VERSION 5.8 ;
BUSBITCHARS "[]" ;
DIVIDERCHAR "/" ;
UNITS
    DATABASE MICRONS 1000 ;
END UNITS

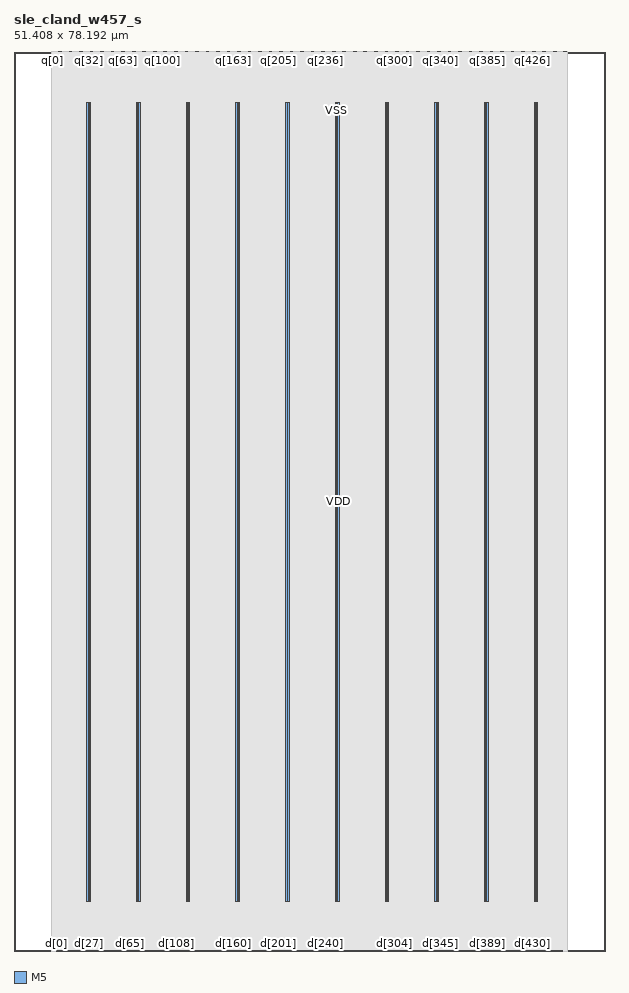
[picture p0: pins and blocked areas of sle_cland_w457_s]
MACRO sle_cland_w457_s
  FOREIGN sle_cland_w457_s 0 0 ;
  CLASS BLOCK ;
  SIZE 51.408 BY 78.192 ;
  PIN clk
    DIRECTION INPUT ;
    USE SIGNAL ;
    PORT
      LAYER M5 ;
        RECT  25.2 78.108 25.224 78.192 ;
    END
  END clk
  PIN d[0]
    DIRECTION INPUT ;
    USE SIGNAL ;
    PORT
      LAYER M5 ;
        RECT  3.696 0 3.72 0.084 ;
    END
  END d[0]
  PIN d[100]
    DIRECTION INPUT ;
    USE SIGNAL ;
    PORT
      LAYER M5 ;
        RECT  13.296 0 13.32 0.084 ;
    END
  END d[100]
  PIN d[101]
    DIRECTION INPUT ;
    USE SIGNAL ;
    PORT
      LAYER M5 ;
        RECT  13.392 0 13.416 0.084 ;
    END
  END d[101]
  PIN d[102]
    DIRECTION INPUT ;
    USE SIGNAL ;
    PORT
      LAYER M5 ;
        RECT  13.488 0 13.512 0.084 ;
    END
  END d[102]
  PIN d[103]
    DIRECTION INPUT ;
    USE SIGNAL ;
    PORT
      LAYER M5 ;
        RECT  13.584 0 13.608 0.084 ;
    END
  END d[103]
  PIN d[104]
    DIRECTION INPUT ;
    USE SIGNAL ;
    PORT
      LAYER M5 ;
        RECT  13.68 0 13.704 0.084 ;
    END
  END d[104]
  PIN d[105]
    DIRECTION INPUT ;
    USE SIGNAL ;
    PORT
      LAYER M5 ;
        RECT  13.776 0 13.8 0.084 ;
    END
  END d[105]
  PIN d[106]
    DIRECTION INPUT ;
    USE SIGNAL ;
    PORT
      LAYER M5 ;
        RECT  13.872 0 13.896 0.084 ;
    END
  END d[106]
  PIN d[107]
    DIRECTION INPUT ;
    USE SIGNAL ;
    PORT
      LAYER M5 ;
        RECT  13.968 0 13.992 0.084 ;
    END
  END d[107]
  PIN d[108]
    DIRECTION INPUT ;
    USE SIGNAL ;
    PORT
      LAYER M5 ;
        RECT  14.064 0 14.088 0.084 ;
    END
  END d[108]
  PIN d[109]
    DIRECTION INPUT ;
    USE SIGNAL ;
    PORT
      LAYER M5 ;
        RECT  14.16 0 14.184 0.084 ;
    END
  END d[109]
  PIN d[10]
    DIRECTION INPUT ;
    USE SIGNAL ;
    PORT
      LAYER M5 ;
        RECT  4.56 0 4.584 0.084 ;
    END
  END d[10]
  PIN d[110]
    DIRECTION INPUT ;
    USE SIGNAL ;
    PORT
      LAYER M5 ;
        RECT  14.256 0 14.28 0.084 ;
    END
  END d[110]
  PIN d[111]
    DIRECTION INPUT ;
    USE SIGNAL ;
    PORT
      LAYER M5 ;
        RECT  14.448 0 14.472 0.084 ;
    END
  END d[111]
  PIN d[112]
    DIRECTION INPUT ;
    USE SIGNAL ;
    PORT
      LAYER M5 ;
        RECT  14.352 0 14.376 0.084 ;
    END
  END d[112]
  PIN d[113]
    DIRECTION INPUT ;
    USE SIGNAL ;
    PORT
      LAYER M5 ;
        RECT  14.64 0 14.664 0.084 ;
    END
  END d[113]
  PIN d[114]
    DIRECTION INPUT ;
    USE SIGNAL ;
    PORT
      LAYER M5 ;
        RECT  14.544 0 14.568 0.084 ;
    END
  END d[114]
  PIN d[115]
    DIRECTION INPUT ;
    USE SIGNAL ;
    PORT
      LAYER M5 ;
        RECT  14.832 0 14.856 0.084 ;
    END
  END d[115]
  PIN d[116]
    DIRECTION INPUT ;
    USE SIGNAL ;
    PORT
      LAYER M5 ;
        RECT  14.736 0 14.76 0.084 ;
    END
  END d[116]
  PIN d[117]
    DIRECTION INPUT ;
    USE SIGNAL ;
    PORT
      LAYER M5 ;
        RECT  15.024 0 15.048 0.084 ;
    END
  END d[117]
  PIN d[118]
    DIRECTION INPUT ;
    USE SIGNAL ;
    PORT
      LAYER M5 ;
        RECT  14.928 0 14.952 0.084 ;
    END
  END d[118]
  PIN d[119]
    DIRECTION INPUT ;
    USE SIGNAL ;
    PORT
      LAYER M5 ;
        RECT  15.312 0 15.336 0.084 ;
    END
  END d[119]
  PIN d[11]
    DIRECTION INPUT ;
    USE SIGNAL ;
    PORT
      LAYER M5 ;
        RECT  4.848 0 4.872 0.084 ;
    END
  END d[11]
  PIN d[120]
    DIRECTION INPUT ;
    USE SIGNAL ;
    PORT
      LAYER M5 ;
        RECT  15.12 0 15.144 0.084 ;
    END
  END d[120]
  PIN d[121]
    DIRECTION INPUT ;
    USE SIGNAL ;
    PORT
      LAYER M5 ;
        RECT  15.408 0 15.432 0.084 ;
    END
  END d[121]
  PIN d[122]
    DIRECTION INPUT ;
    USE SIGNAL ;
    PORT
      LAYER M5 ;
        RECT  15.216 0 15.24 0.084 ;
    END
  END d[122]
  PIN d[123]
    DIRECTION INPUT ;
    USE SIGNAL ;
    PORT
      LAYER M5 ;
        RECT  15.6 0 15.624 0.084 ;
    END
  END d[123]
  PIN d[124]
    DIRECTION INPUT ;
    USE SIGNAL ;
    PORT
      LAYER M5 ;
        RECT  15.504 0 15.528 0.084 ;
    END
  END d[124]
  PIN d[125]
    DIRECTION INPUT ;
    USE SIGNAL ;
    PORT
      LAYER M5 ;
        RECT  15.792 0 15.816 0.084 ;
    END
  END d[125]
  PIN d[126]
    DIRECTION INPUT ;
    USE SIGNAL ;
    PORT
      LAYER M5 ;
        RECT  15.696 0 15.72 0.084 ;
    END
  END d[126]
  PIN d[127]
    DIRECTION INPUT ;
    USE SIGNAL ;
    PORT
      LAYER M5 ;
        RECT  16.08 0 16.104 0.084 ;
    END
  END d[127]
  PIN d[128]
    DIRECTION INPUT ;
    USE SIGNAL ;
    PORT
      LAYER M5 ;
        RECT  15.888 0 15.912 0.084 ;
    END
  END d[128]
  PIN d[129]
    DIRECTION INPUT ;
    USE SIGNAL ;
    PORT
      LAYER M5 ;
        RECT  16.176 0 16.2 0.084 ;
    END
  END d[129]
  PIN d[12]
    DIRECTION INPUT ;
    USE SIGNAL ;
    PORT
      LAYER M5 ;
        RECT  4.752 0 4.776 0.084 ;
    END
  END d[12]
  PIN d[130]
    DIRECTION INPUT ;
    USE SIGNAL ;
    PORT
      LAYER M5 ;
        RECT  15.984 0 16.008 0.084 ;
    END
  END d[130]
  PIN d[131]
    DIRECTION INPUT ;
    USE SIGNAL ;
    PORT
      LAYER M5 ;
        RECT  16.272 0 16.296 0.084 ;
    END
  END d[131]
  PIN d[132]
    DIRECTION INPUT ;
    USE SIGNAL ;
    PORT
      LAYER M5 ;
        RECT  16.464 0 16.488 0.084 ;
    END
  END d[132]
  PIN d[133]
    DIRECTION INPUT ;
    USE SIGNAL ;
    PORT
      LAYER M5 ;
        RECT  16.368 0 16.392 0.084 ;
    END
  END d[133]
  PIN d[134]
    DIRECTION INPUT ;
    USE SIGNAL ;
    PORT
      LAYER M5 ;
        RECT  16.656 0 16.68 0.084 ;
    END
  END d[134]
  PIN d[135]
    DIRECTION INPUT ;
    USE SIGNAL ;
    PORT
      LAYER M5 ;
        RECT  16.56 0 16.584 0.084 ;
    END
  END d[135]
  PIN d[136]
    DIRECTION INPUT ;
    USE SIGNAL ;
    PORT
      LAYER M5 ;
        RECT  16.848 0 16.872 0.084 ;
    END
  END d[136]
  PIN d[137]
    DIRECTION INPUT ;
    USE SIGNAL ;
    PORT
      LAYER M5 ;
        RECT  16.752 0 16.776 0.084 ;
    END
  END d[137]
  PIN d[138]
    DIRECTION INPUT ;
    USE SIGNAL ;
    PORT
      LAYER M5 ;
        RECT  17.04 0 17.064 0.084 ;
    END
  END d[138]
  PIN d[139]
    DIRECTION INPUT ;
    USE SIGNAL ;
    PORT
      LAYER M5 ;
        RECT  16.944 0 16.968 0.084 ;
    END
  END d[139]
  PIN d[13]
    DIRECTION INPUT ;
    USE SIGNAL ;
    PORT
      LAYER M5 ;
        RECT  5.04 0 5.064 0.084 ;
    END
  END d[13]
  PIN d[140]
    DIRECTION INPUT ;
    USE SIGNAL ;
    PORT
      LAYER M5 ;
        RECT  17.232 0 17.256 0.084 ;
    END
  END d[140]
  PIN d[141]
    DIRECTION INPUT ;
    USE SIGNAL ;
    PORT
      LAYER M5 ;
        RECT  17.136 0 17.16 0.084 ;
    END
  END d[141]
  PIN d[142]
    DIRECTION INPUT ;
    USE SIGNAL ;
    PORT
      LAYER M5 ;
        RECT  17.424 0 17.448 0.084 ;
    END
  END d[142]
  PIN d[143]
    DIRECTION INPUT ;
    USE SIGNAL ;
    PORT
      LAYER M5 ;
        RECT  17.328 0 17.352 0.084 ;
    END
  END d[143]
  PIN d[144]
    DIRECTION INPUT ;
    USE SIGNAL ;
    PORT
      LAYER M5 ;
        RECT  17.616 0 17.64 0.084 ;
    END
  END d[144]
  PIN d[145]
    DIRECTION INPUT ;
    USE SIGNAL ;
    PORT
      LAYER M5 ;
        RECT  17.52 0 17.544 0.084 ;
    END
  END d[145]
  PIN d[146]
    DIRECTION INPUT ;
    USE SIGNAL ;
    PORT
      LAYER M5 ;
        RECT  17.712 0 17.736 0.084 ;
    END
  END d[146]
  PIN d[147]
    DIRECTION INPUT ;
    USE SIGNAL ;
    PORT
      LAYER M5 ;
        RECT  17.808 0 17.832 0.084 ;
    END
  END d[147]
  PIN d[148]
    DIRECTION INPUT ;
    USE SIGNAL ;
    PORT
      LAYER M5 ;
        RECT  17.904 0 17.928 0.084 ;
    END
  END d[148]
  PIN d[149]
    DIRECTION INPUT ;
    USE SIGNAL ;
    PORT
      LAYER M5 ;
        RECT  18 0 18.024 0.084 ;
    END
  END d[149]
  PIN d[14]
    DIRECTION INPUT ;
    USE SIGNAL ;
    PORT
      LAYER M5 ;
        RECT  4.944 0 4.968 0.084 ;
    END
  END d[14]
  PIN d[150]
    DIRECTION INPUT ;
    USE SIGNAL ;
    PORT
      LAYER M5 ;
        RECT  18.096 0 18.12 0.084 ;
    END
  END d[150]
  PIN d[151]
    DIRECTION INPUT ;
    USE SIGNAL ;
    PORT
      LAYER M5 ;
        RECT  18.192 0 18.216 0.084 ;
    END
  END d[151]
  PIN d[152]
    DIRECTION INPUT ;
    USE SIGNAL ;
    PORT
      LAYER M5 ;
        RECT  18.288 0 18.312 0.084 ;
    END
  END d[152]
  PIN d[153]
    DIRECTION INPUT ;
    USE SIGNAL ;
    PORT
      LAYER M5 ;
        RECT  18.384 0 18.408 0.084 ;
    END
  END d[153]
  PIN d[154]
    DIRECTION INPUT ;
    USE SIGNAL ;
    PORT
      LAYER M5 ;
        RECT  18.48 0 18.504 0.084 ;
    END
  END d[154]
  PIN d[155]
    DIRECTION INPUT ;
    USE SIGNAL ;
    PORT
      LAYER M5 ;
        RECT  18.576 0 18.6 0.084 ;
    END
  END d[155]
  PIN d[156]
    DIRECTION INPUT ;
    USE SIGNAL ;
    PORT
      LAYER M5 ;
        RECT  18.672 0 18.696 0.084 ;
    END
  END d[156]
  PIN d[157]
    DIRECTION INPUT ;
    USE SIGNAL ;
    PORT
      LAYER M5 ;
        RECT  18.768 0 18.792 0.084 ;
    END
  END d[157]
  PIN d[158]
    DIRECTION INPUT ;
    USE SIGNAL ;
    PORT
      LAYER M5 ;
        RECT  18.864 0 18.888 0.084 ;
    END
  END d[158]
  PIN d[159]
    DIRECTION INPUT ;
    USE SIGNAL ;
    PORT
      LAYER M5 ;
        RECT  18.96 0 18.984 0.084 ;
    END
  END d[159]
  PIN d[15]
    DIRECTION INPUT ;
    USE SIGNAL ;
    PORT
      LAYER M5 ;
        RECT  5.232 0 5.256 0.084 ;
    END
  END d[15]
  PIN d[160]
    DIRECTION INPUT ;
    USE SIGNAL ;
    PORT
      LAYER M5 ;
        RECT  19.056 0 19.08 0.084 ;
    END
  END d[160]
  PIN d[161]
    DIRECTION INPUT ;
    USE SIGNAL ;
    PORT
      LAYER M5 ;
        RECT  19.152 0 19.176 0.084 ;
    END
  END d[161]
  PIN d[162]
    DIRECTION INPUT ;
    USE SIGNAL ;
    PORT
      LAYER M5 ;
        RECT  19.248 0 19.272 0.084 ;
    END
  END d[162]
  PIN d[163]
    DIRECTION INPUT ;
    USE SIGNAL ;
    PORT
      LAYER M5 ;
        RECT  19.44 0 19.464 0.084 ;
    END
  END d[163]
  PIN d[164]
    DIRECTION INPUT ;
    USE SIGNAL ;
    PORT
      LAYER M5 ;
        RECT  19.344 0 19.368 0.084 ;
    END
  END d[164]
  PIN d[165]
    DIRECTION INPUT ;
    USE SIGNAL ;
    PORT
      LAYER M5 ;
        RECT  19.632 0 19.656 0.084 ;
    END
  END d[165]
  PIN d[166]
    DIRECTION INPUT ;
    USE SIGNAL ;
    PORT
      LAYER M5 ;
        RECT  19.536 0 19.56 0.084 ;
    END
  END d[166]
  PIN d[167]
    DIRECTION INPUT ;
    USE SIGNAL ;
    PORT
      LAYER M5 ;
        RECT  19.824 0 19.848 0.084 ;
    END
  END d[167]
  PIN d[168]
    DIRECTION INPUT ;
    USE SIGNAL ;
    PORT
      LAYER M5 ;
        RECT  19.728 0 19.752 0.084 ;
    END
  END d[168]
  PIN d[169]
    DIRECTION INPUT ;
    USE SIGNAL ;
    PORT
      LAYER M5 ;
        RECT  20.112 0 20.136 0.084 ;
    END
  END d[169]
  PIN d[16]
    DIRECTION INPUT ;
    USE SIGNAL ;
    PORT
      LAYER M5 ;
        RECT  5.136 0 5.16 0.084 ;
    END
  END d[16]
  PIN d[170]
    DIRECTION INPUT ;
    USE SIGNAL ;
    PORT
      LAYER M5 ;
        RECT  19.92 0 19.944 0.084 ;
    END
  END d[170]
  PIN d[171]
    DIRECTION INPUT ;
    USE SIGNAL ;
    PORT
      LAYER M5 ;
        RECT  20.208 0 20.232 0.084 ;
    END
  END d[171]
  PIN d[172]
    DIRECTION INPUT ;
    USE SIGNAL ;
    PORT
      LAYER M5 ;
        RECT  20.016 0 20.04 0.084 ;
    END
  END d[172]
  PIN d[173]
    DIRECTION INPUT ;
    USE SIGNAL ;
    PORT
      LAYER M5 ;
        RECT  20.4 0 20.424 0.084 ;
    END
  END d[173]
  PIN d[174]
    DIRECTION INPUT ;
    USE SIGNAL ;
    PORT
      LAYER M5 ;
        RECT  20.304 0 20.328 0.084 ;
    END
  END d[174]
  PIN d[175]
    DIRECTION INPUT ;
    USE SIGNAL ;
    PORT
      LAYER M5 ;
        RECT  20.592 0 20.616 0.084 ;
    END
  END d[175]
  PIN d[176]
    DIRECTION INPUT ;
    USE SIGNAL ;
    PORT
      LAYER M5 ;
        RECT  20.496 0 20.52 0.084 ;
    END
  END d[176]
  PIN d[177]
    DIRECTION INPUT ;
    USE SIGNAL ;
    PORT
      LAYER M5 ;
        RECT  20.88 0 20.904 0.084 ;
    END
  END d[177]
  PIN d[178]
    DIRECTION INPUT ;
    USE SIGNAL ;
    PORT
      LAYER M5 ;
        RECT  20.688 0 20.712 0.084 ;
    END
  END d[178]
  PIN d[179]
    DIRECTION INPUT ;
    USE SIGNAL ;
    PORT
      LAYER M5 ;
        RECT  20.976 0 21 0.084 ;
    END
  END d[179]
  PIN d[17]
    DIRECTION INPUT ;
    USE SIGNAL ;
    PORT
      LAYER M5 ;
        RECT  5.424 0 5.448 0.084 ;
    END
  END d[17]
  PIN d[180]
    DIRECTION INPUT ;
    USE SIGNAL ;
    PORT
      LAYER M5 ;
        RECT  20.784 0 20.808 0.084 ;
    END
  END d[180]
  PIN d[181]
    DIRECTION INPUT ;
    USE SIGNAL ;
    PORT
      LAYER M5 ;
        RECT  21.072 0 21.096 0.084 ;
    END
  END d[181]
  PIN d[182]
    DIRECTION INPUT ;
    USE SIGNAL ;
    PORT
      LAYER M5 ;
        RECT  21.264 0 21.288 0.084 ;
    END
  END d[182]
  PIN d[183]
    DIRECTION INPUT ;
    USE SIGNAL ;
    PORT
      LAYER M5 ;
        RECT  21.168 0 21.192 0.084 ;
    END
  END d[183]
  PIN d[184]
    DIRECTION INPUT ;
    USE SIGNAL ;
    PORT
      LAYER M5 ;
        RECT  21.456 0 21.48 0.084 ;
    END
  END d[184]
  PIN d[185]
    DIRECTION INPUT ;
    USE SIGNAL ;
    PORT
      LAYER M5 ;
        RECT  21.36 0 21.384 0.084 ;
    END
  END d[185]
  PIN d[186]
    DIRECTION INPUT ;
    USE SIGNAL ;
    PORT
      LAYER M5 ;
        RECT  21.648 0 21.672 0.084 ;
    END
  END d[186]
  PIN d[187]
    DIRECTION INPUT ;
    USE SIGNAL ;
    PORT
      LAYER M5 ;
        RECT  21.552 0 21.576 0.084 ;
    END
  END d[187]
  PIN d[188]
    DIRECTION INPUT ;
    USE SIGNAL ;
    PORT
      LAYER M5 ;
        RECT  21.84 0 21.864 0.084 ;
    END
  END d[188]
  PIN d[189]
    DIRECTION INPUT ;
    USE SIGNAL ;
    PORT
      LAYER M5 ;
        RECT  21.744 0 21.768 0.084 ;
    END
  END d[189]
  PIN d[18]
    DIRECTION INPUT ;
    USE SIGNAL ;
    PORT
      LAYER M5 ;
        RECT  5.328 0 5.352 0.084 ;
    END
  END d[18]
  PIN d[190]
    DIRECTION INPUT ;
    USE SIGNAL ;
    PORT
      LAYER M5 ;
        RECT  22.032 0 22.056 0.084 ;
    END
  END d[190]
  PIN d[191]
    DIRECTION INPUT ;
    USE SIGNAL ;
    PORT
      LAYER M5 ;
        RECT  21.936 0 21.96 0.084 ;
    END
  END d[191]
  PIN d[192]
    DIRECTION INPUT ;
    USE SIGNAL ;
    PORT
      LAYER M5 ;
        RECT  22.224 0 22.248 0.084 ;
    END
  END d[192]
  PIN d[193]
    DIRECTION INPUT ;
    USE SIGNAL ;
    PORT
      LAYER M5 ;
        RECT  22.128 0 22.152 0.084 ;
    END
  END d[193]
  PIN d[194]
    DIRECTION INPUT ;
    USE SIGNAL ;
    PORT
      LAYER M5 ;
        RECT  22.32 0 22.344 0.084 ;
    END
  END d[194]
  PIN d[195]
    DIRECTION INPUT ;
    USE SIGNAL ;
    PORT
      LAYER M5 ;
        RECT  22.416 0 22.44 0.084 ;
    END
  END d[195]
  PIN d[196]
    DIRECTION INPUT ;
    USE SIGNAL ;
    PORT
      LAYER M5 ;
        RECT  22.512 0 22.536 0.084 ;
    END
  END d[196]
  PIN d[197]
    DIRECTION INPUT ;
    USE SIGNAL ;
    PORT
      LAYER M5 ;
        RECT  22.608 0 22.632 0.084 ;
    END
  END d[197]
  PIN d[198]
    DIRECTION INPUT ;
    USE SIGNAL ;
    PORT
      LAYER M5 ;
        RECT  22.704 0 22.728 0.084 ;
    END
  END d[198]
  PIN d[199]
    DIRECTION INPUT ;
    USE SIGNAL ;
    PORT
      LAYER M5 ;
        RECT  22.8 0 22.824 0.084 ;
    END
  END d[199]
  PIN d[19]
    DIRECTION INPUT ;
    USE SIGNAL ;
    PORT
      LAYER M5 ;
        RECT  5.616 0 5.64 0.084 ;
    END
  END d[19]
  PIN d[1]
    DIRECTION INPUT ;
    USE SIGNAL ;
    PORT
      LAYER M5 ;
        RECT  3.792 0 3.816 0.084 ;
    END
  END d[1]
  PIN d[200]
    DIRECTION INPUT ;
    USE SIGNAL ;
    PORT
      LAYER M5 ;
        RECT  22.896 0 22.92 0.084 ;
    END
  END d[200]
  PIN d[201]
    DIRECTION INPUT ;
    USE SIGNAL ;
    PORT
      LAYER M5 ;
        RECT  22.992 0 23.016 0.084 ;
    END
  END d[201]
  PIN d[202]
    DIRECTION INPUT ;
    USE SIGNAL ;
    PORT
      LAYER M5 ;
        RECT  23.088 0 23.112 0.084 ;
    END
  END d[202]
  PIN d[203]
    DIRECTION INPUT ;
    USE SIGNAL ;
    PORT
      LAYER M5 ;
        RECT  23.184 0 23.208 0.084 ;
    END
  END d[203]
  PIN d[204]
    DIRECTION INPUT ;
    USE SIGNAL ;
    PORT
      LAYER M5 ;
        RECT  23.28 0 23.304 0.084 ;
    END
  END d[204]
  PIN d[205]
    DIRECTION INPUT ;
    USE SIGNAL ;
    PORT
      LAYER M5 ;
        RECT  23.376 0 23.4 0.084 ;
    END
  END d[205]
  PIN d[206]
    DIRECTION INPUT ;
    USE SIGNAL ;
    PORT
      LAYER M5 ;
        RECT  23.472 0 23.496 0.084 ;
    END
  END d[206]
  PIN d[207]
    DIRECTION INPUT ;
    USE SIGNAL ;
    PORT
      LAYER M5 ;
        RECT  23.568 0 23.592 0.084 ;
    END
  END d[207]
  PIN d[208]
    DIRECTION INPUT ;
    USE SIGNAL ;
    PORT
      LAYER M5 ;
        RECT  23.664 0 23.688 0.084 ;
    END
  END d[208]
  PIN d[209]
    DIRECTION INPUT ;
    USE SIGNAL ;
    PORT
      LAYER M5 ;
        RECT  23.76 0 23.784 0.084 ;
    END
  END d[209]
  PIN d[20]
    DIRECTION INPUT ;
    USE SIGNAL ;
    PORT
      LAYER M5 ;
        RECT  5.52 0 5.544 0.084 ;
    END
  END d[20]
  PIN d[210]
    DIRECTION INPUT ;
    USE SIGNAL ;
    PORT
      LAYER M5 ;
        RECT  23.856 0 23.88 0.084 ;
    END
  END d[210]
  PIN d[211]
    DIRECTION INPUT ;
    USE SIGNAL ;
    PORT
      LAYER M5 ;
        RECT  23.952 0 23.976 0.084 ;
    END
  END d[211]
  PIN d[212]
    DIRECTION INPUT ;
    USE SIGNAL ;
    PORT
      LAYER M5 ;
        RECT  24.048 0 24.072 0.084 ;
    END
  END d[212]
  PIN d[213]
    DIRECTION INPUT ;
    USE SIGNAL ;
    PORT
      LAYER M5 ;
        RECT  24.24 0 24.264 0.084 ;
    END
  END d[213]
  PIN d[214]
    DIRECTION INPUT ;
    USE SIGNAL ;
    PORT
      LAYER M5 ;
        RECT  24.144 0 24.168 0.084 ;
    END
  END d[214]
  PIN d[215]
    DIRECTION INPUT ;
    USE SIGNAL ;
    PORT
      LAYER M5 ;
        RECT  24.432 0 24.456 0.084 ;
    END
  END d[215]
  PIN d[216]
    DIRECTION INPUT ;
    USE SIGNAL ;
    PORT
      LAYER M5 ;
        RECT  24.336 0 24.36 0.084 ;
    END
  END d[216]
  PIN d[217]
    DIRECTION INPUT ;
    USE SIGNAL ;
    PORT
      LAYER M5 ;
        RECT  24.624 0 24.648 0.084 ;
    END
  END d[217]
  PIN d[218]
    DIRECTION INPUT ;
    USE SIGNAL ;
    PORT
      LAYER M5 ;
        RECT  24.528 0 24.552 0.084 ;
    END
  END d[218]
  PIN d[219]
    DIRECTION INPUT ;
    USE SIGNAL ;
    PORT
      LAYER M5 ;
        RECT  24.912 0 24.936 0.084 ;
    END
  END d[219]
  PIN d[21]
    DIRECTION INPUT ;
    USE SIGNAL ;
    PORT
      LAYER M5 ;
        RECT  5.808 0 5.832 0.084 ;
    END
  END d[21]
  PIN d[220]
    DIRECTION INPUT ;
    USE SIGNAL ;
    PORT
      LAYER M5 ;
        RECT  24.72 0 24.744 0.084 ;
    END
  END d[220]
  PIN d[221]
    DIRECTION INPUT ;
    USE SIGNAL ;
    PORT
      LAYER M5 ;
        RECT  25.008 0 25.032 0.084 ;
    END
  END d[221]
  PIN d[222]
    DIRECTION INPUT ;
    USE SIGNAL ;
    PORT
      LAYER M5 ;
        RECT  24.816 0 24.84 0.084 ;
    END
  END d[222]
  PIN d[223]
    DIRECTION INPUT ;
    USE SIGNAL ;
    PORT
      LAYER M5 ;
        RECT  25.2 0 25.224 0.084 ;
    END
  END d[223]
  PIN d[224]
    DIRECTION INPUT ;
    USE SIGNAL ;
    PORT
      LAYER M5 ;
        RECT  25.104 0 25.128 0.084 ;
    END
  END d[224]
  PIN d[225]
    DIRECTION INPUT ;
    USE SIGNAL ;
    PORT
      LAYER M5 ;
        RECT  25.392 0 25.416 0.084 ;
    END
  END d[225]
  PIN d[226]
    DIRECTION INPUT ;
    USE SIGNAL ;
    PORT
      LAYER M5 ;
        RECT  25.296 0 25.32 0.084 ;
    END
  END d[226]
  PIN d[227]
    DIRECTION INPUT ;
    USE SIGNAL ;
    PORT
      LAYER M5 ;
        RECT  25.776 0 25.8 0.084 ;
    END
  END d[227]
  PIN d[228]
    DIRECTION INPUT ;
    USE SIGNAL ;
    PORT
      LAYER M5 ;
        RECT  25.488 0 25.512 0.084 ;
    END
  END d[228]
  PIN d[229]
    DIRECTION INPUT ;
    USE SIGNAL ;
    PORT
      LAYER M5 ;
        RECT  25.968 0 25.992 0.084 ;
    END
  END d[229]
  PIN d[22]
    DIRECTION INPUT ;
    USE SIGNAL ;
    PORT
      LAYER M5 ;
        RECT  5.712 0 5.736 0.084 ;
    END
  END d[22]
  PIN d[230]
    DIRECTION INPUT ;
    USE SIGNAL ;
    PORT
      LAYER M5 ;
        RECT  25.872 0 25.896 0.084 ;
    END
  END d[230]
  PIN d[231]
    DIRECTION INPUT ;
    USE SIGNAL ;
    PORT
      LAYER M5 ;
        RECT  26.064 0 26.088 0.084 ;
    END
  END d[231]
  PIN d[232]
    DIRECTION INPUT ;
    USE SIGNAL ;
    PORT
      LAYER M5 ;
        RECT  26.256 0 26.28 0.084 ;
    END
  END d[232]
  PIN d[233]
    DIRECTION INPUT ;
    USE SIGNAL ;
    PORT
      LAYER M5 ;
        RECT  26.16 0 26.184 0.084 ;
    END
  END d[233]
  PIN d[234]
    DIRECTION INPUT ;
    USE SIGNAL ;
    PORT
      LAYER M5 ;
        RECT  26.448 0 26.472 0.084 ;
    END
  END d[234]
  PIN d[235]
    DIRECTION INPUT ;
    USE SIGNAL ;
    PORT
      LAYER M5 ;
        RECT  26.352 0 26.376 0.084 ;
    END
  END d[235]
  PIN d[236]
    DIRECTION INPUT ;
    USE SIGNAL ;
    PORT
      LAYER M5 ;
        RECT  26.64 0 26.664 0.084 ;
    END
  END d[236]
  PIN d[237]
    DIRECTION INPUT ;
    USE SIGNAL ;
    PORT
      LAYER M5 ;
        RECT  26.544 0 26.568 0.084 ;
    END
  END d[237]
  PIN d[238]
    DIRECTION INPUT ;
    USE SIGNAL ;
    PORT
      LAYER M5 ;
        RECT  26.832 0 26.856 0.084 ;
    END
  END d[238]
  PIN d[239]
    DIRECTION INPUT ;
    USE SIGNAL ;
    PORT
      LAYER M5 ;
        RECT  26.736 0 26.76 0.084 ;
    END
  END d[239]
  PIN d[23]
    DIRECTION INPUT ;
    USE SIGNAL ;
    PORT
      LAYER M5 ;
        RECT  6 0 6.024 0.084 ;
    END
  END d[23]
  PIN d[240]
    DIRECTION INPUT ;
    USE SIGNAL ;
    PORT
      LAYER M5 ;
        RECT  27.024 0 27.048 0.084 ;
    END
  END d[240]
  PIN d[241]
    DIRECTION INPUT ;
    USE SIGNAL ;
    PORT
      LAYER M5 ;
        RECT  26.928 0 26.952 0.084 ;
    END
  END d[241]
  PIN d[242]
    DIRECTION INPUT ;
    USE SIGNAL ;
    PORT
      LAYER M5 ;
        RECT  27.216 0 27.24 0.084 ;
    END
  END d[242]
  PIN d[243]
    DIRECTION INPUT ;
    USE SIGNAL ;
    PORT
      LAYER M5 ;
        RECT  27.12 0 27.144 0.084 ;
    END
  END d[243]
  PIN d[244]
    DIRECTION INPUT ;
    USE SIGNAL ;
    PORT
      LAYER M5 ;
        RECT  27.312 0 27.336 0.084 ;
    END
  END d[244]
  PIN d[245]
    DIRECTION INPUT ;
    USE SIGNAL ;
    PORT
      LAYER M5 ;
        RECT  27.408 0 27.432 0.084 ;
    END
  END d[245]
  PIN d[246]
    DIRECTION INPUT ;
    USE SIGNAL ;
    PORT
      LAYER M5 ;
        RECT  27.6 0 27.624 0.084 ;
    END
  END d[246]
  PIN d[247]
    DIRECTION INPUT ;
    USE SIGNAL ;
    PORT
      LAYER M5 ;
        RECT  27.504 0 27.528 0.084 ;
    END
  END d[247]
  PIN d[248]
    DIRECTION INPUT ;
    USE SIGNAL ;
    PORT
      LAYER M5 ;
        RECT  27.792 0 27.816 0.084 ;
    END
  END d[248]
  PIN d[249]
    DIRECTION INPUT ;
    USE SIGNAL ;
    PORT
      LAYER M5 ;
        RECT  27.696 0 27.72 0.084 ;
    END
  END d[249]
  PIN d[24]
    DIRECTION INPUT ;
    USE SIGNAL ;
    PORT
      LAYER M5 ;
        RECT  5.904 0 5.928 0.084 ;
    END
  END d[24]
  PIN d[250]
    DIRECTION INPUT ;
    USE SIGNAL ;
    PORT
      LAYER M5 ;
        RECT  27.888 0 27.912 0.084 ;
    END
  END d[250]
  PIN d[251]
    DIRECTION INPUT ;
    USE SIGNAL ;
    PORT
      LAYER M5 ;
        RECT  27.984 0 28.008 0.084 ;
    END
  END d[251]
  PIN d[252]
    DIRECTION INPUT ;
    USE SIGNAL ;
    PORT
      LAYER M5 ;
        RECT  28.08 0 28.104 0.084 ;
    END
  END d[252]
  PIN d[253]
    DIRECTION INPUT ;
    USE SIGNAL ;
    PORT
      LAYER M5 ;
        RECT  28.176 0 28.2 0.084 ;
    END
  END d[253]
  PIN d[254]
    DIRECTION INPUT ;
    USE SIGNAL ;
    PORT
      LAYER M5 ;
        RECT  28.272 0 28.296 0.084 ;
    END
  END d[254]
  PIN d[255]
    DIRECTION INPUT ;
    USE SIGNAL ;
    PORT
      LAYER M5 ;
        RECT  28.368 0 28.392 0.084 ;
    END
  END d[255]
  PIN d[256]
    DIRECTION INPUT ;
    USE SIGNAL ;
    PORT
      LAYER M5 ;
        RECT  28.464 0 28.488 0.084 ;
    END
  END d[256]
  PIN d[257]
    DIRECTION INPUT ;
    USE SIGNAL ;
    PORT
      LAYER M5 ;
        RECT  28.56 0 28.584 0.084 ;
    END
  END d[257]
  PIN d[258]
    DIRECTION INPUT ;
    USE SIGNAL ;
    PORT
      LAYER M5 ;
        RECT  28.656 0 28.68 0.084 ;
    END
  END d[258]
  PIN d[259]
    DIRECTION INPUT ;
    USE SIGNAL ;
    PORT
      LAYER M5 ;
        RECT  28.752 0 28.776 0.084 ;
    END
  END d[259]
  PIN d[25]
    DIRECTION INPUT ;
    USE SIGNAL ;
    PORT
      LAYER M5 ;
        RECT  6.288 0 6.312 0.084 ;
    END
  END d[25]
  PIN d[260]
    DIRECTION INPUT ;
    USE SIGNAL ;
    PORT
      LAYER M5 ;
        RECT  28.848 0 28.872 0.084 ;
    END
  END d[260]
  PIN d[261]
    DIRECTION INPUT ;
    USE SIGNAL ;
    PORT
      LAYER M5 ;
        RECT  28.944 0 28.968 0.084 ;
    END
  END d[261]
  PIN d[262]
    DIRECTION INPUT ;
    USE SIGNAL ;
    PORT
      LAYER M5 ;
        RECT  29.04 0 29.064 0.084 ;
    END
  END d[262]
  PIN d[263]
    DIRECTION INPUT ;
    USE SIGNAL ;
    PORT
      LAYER M5 ;
        RECT  29.136 0 29.16 0.084 ;
    END
  END d[263]
  PIN d[264]
    DIRECTION INPUT ;
    USE SIGNAL ;
    PORT
      LAYER M5 ;
        RECT  29.232 0 29.256 0.084 ;
    END
  END d[264]
  PIN d[265]
    DIRECTION INPUT ;
    USE SIGNAL ;
    PORT
      LAYER M5 ;
        RECT  29.328 0 29.352 0.084 ;
    END
  END d[265]
  PIN d[266]
    DIRECTION INPUT ;
    USE SIGNAL ;
    PORT
      LAYER M5 ;
        RECT  29.424 0 29.448 0.084 ;
    END
  END d[266]
  PIN d[267]
    DIRECTION INPUT ;
    USE SIGNAL ;
    PORT
      LAYER M5 ;
        RECT  29.616 0 29.64 0.084 ;
    END
  END d[267]
  PIN d[268]
    DIRECTION INPUT ;
    USE SIGNAL ;
    PORT
      LAYER M5 ;
        RECT  29.52 0 29.544 0.084 ;
    END
  END d[268]
  PIN d[269]
    DIRECTION INPUT ;
    USE SIGNAL ;
    PORT
      LAYER M5 ;
        RECT  29.712 0 29.736 0.084 ;
    END
  END d[269]
  PIN d[26]
    DIRECTION INPUT ;
    USE SIGNAL ;
    PORT
      LAYER M5 ;
        RECT  6.096 0 6.12 0.084 ;
    END
  END d[26]
  PIN d[270]
    DIRECTION INPUT ;
    USE SIGNAL ;
    PORT
      LAYER M5 ;
        RECT  29.808 0 29.832 0.084 ;
    END
  END d[270]
  PIN d[271]
    DIRECTION INPUT ;
    USE SIGNAL ;
    PORT
      LAYER M5 ;
        RECT  30 0 30.024 0.084 ;
    END
  END d[271]
  PIN d[272]
    DIRECTION INPUT ;
    USE SIGNAL ;
    PORT
      LAYER M5 ;
        RECT  29.904 0 29.928 0.084 ;
    END
  END d[272]
  PIN d[273]
    DIRECTION INPUT ;
    USE SIGNAL ;
    PORT
      LAYER M5 ;
        RECT  30.192 0 30.216 0.084 ;
    END
  END d[273]
  PIN d[274]
    DIRECTION INPUT ;
    USE SIGNAL ;
    PORT
      LAYER M5 ;
        RECT  30.096 0 30.12 0.084 ;
    END
  END d[274]
  PIN d[275]
    DIRECTION INPUT ;
    USE SIGNAL ;
    PORT
      LAYER M5 ;
        RECT  30.384 0 30.408 0.084 ;
    END
  END d[275]
  PIN d[276]
    DIRECTION INPUT ;
    USE SIGNAL ;
    PORT
      LAYER M5 ;
        RECT  30.288 0 30.312 0.084 ;
    END
  END d[276]
  PIN d[277]
    DIRECTION INPUT ;
    USE SIGNAL ;
    PORT
      LAYER M5 ;
        RECT  30.576 0 30.6 0.084 ;
    END
  END d[277]
  PIN d[278]
    DIRECTION INPUT ;
    USE SIGNAL ;
    PORT
      LAYER M5 ;
        RECT  30.48 0 30.504 0.084 ;
    END
  END d[278]
  PIN d[279]
    DIRECTION INPUT ;
    USE SIGNAL ;
    PORT
      LAYER M5 ;
        RECT  30.768 0 30.792 0.084 ;
    END
  END d[279]
  PIN d[27]
    DIRECTION INPUT ;
    USE SIGNAL ;
    PORT
      LAYER M5 ;
        RECT  6.48 0 6.504 0.084 ;
    END
  END d[27]
  PIN d[280]
    DIRECTION INPUT ;
    USE SIGNAL ;
    PORT
      LAYER M5 ;
        RECT  30.672 0 30.696 0.084 ;
    END
  END d[280]
  PIN d[281]
    DIRECTION INPUT ;
    USE SIGNAL ;
    PORT
      LAYER M5 ;
        RECT  30.864 0 30.888 0.084 ;
    END
  END d[281]
  PIN d[282]
    DIRECTION INPUT ;
    USE SIGNAL ;
    PORT
      LAYER M5 ;
        RECT  31.056 0 31.08 0.084 ;
    END
  END d[282]
  PIN d[283]
    DIRECTION INPUT ;
    USE SIGNAL ;
    PORT
      LAYER M5 ;
        RECT  30.96 0 30.984 0.084 ;
    END
  END d[283]
  PIN d[284]
    DIRECTION INPUT ;
    USE SIGNAL ;
    PORT
      LAYER M5 ;
        RECT  31.248 0 31.272 0.084 ;
    END
  END d[284]
  PIN d[285]
    DIRECTION INPUT ;
    USE SIGNAL ;
    PORT
      LAYER M5 ;
        RECT  31.152 0 31.176 0.084 ;
    END
  END d[285]
  PIN d[286]
    DIRECTION INPUT ;
    USE SIGNAL ;
    PORT
      LAYER M5 ;
        RECT  31.44 0 31.464 0.084 ;
    END
  END d[286]
  PIN d[287]
    DIRECTION INPUT ;
    USE SIGNAL ;
    PORT
      LAYER M5 ;
        RECT  31.344 0 31.368 0.084 ;
    END
  END d[287]
  PIN d[288]
    DIRECTION INPUT ;
    USE SIGNAL ;
    PORT
      LAYER M5 ;
        RECT  31.632 0 31.656 0.084 ;
    END
  END d[288]
  PIN d[289]
    DIRECTION INPUT ;
    USE SIGNAL ;
    PORT
      LAYER M5 ;
        RECT  31.536 0 31.56 0.084 ;
    END
  END d[289]
  PIN d[28]
    DIRECTION INPUT ;
    USE SIGNAL ;
    PORT
      LAYER M5 ;
        RECT  6.192 0 6.216 0.084 ;
    END
  END d[28]
  PIN d[290]
    DIRECTION INPUT ;
    USE SIGNAL ;
    PORT
      LAYER M5 ;
        RECT  31.824 0 31.848 0.084 ;
    END
  END d[290]
  PIN d[291]
    DIRECTION INPUT ;
    USE SIGNAL ;
    PORT
      LAYER M5 ;
        RECT  31.728 0 31.752 0.084 ;
    END
  END d[291]
  PIN d[292]
    DIRECTION INPUT ;
    USE SIGNAL ;
    PORT
      LAYER M5 ;
        RECT  32.016 0 32.04 0.084 ;
    END
  END d[292]
  PIN d[293]
    DIRECTION INPUT ;
    USE SIGNAL ;
    PORT
      LAYER M5 ;
        RECT  31.92 0 31.944 0.084 ;
    END
  END d[293]
  PIN d[294]
    DIRECTION INPUT ;
    USE SIGNAL ;
    PORT
      LAYER M5 ;
        RECT  32.112 0 32.136 0.084 ;
    END
  END d[294]
  PIN d[295]
    DIRECTION INPUT ;
    USE SIGNAL ;
    PORT
      LAYER M5 ;
        RECT  32.208 0 32.232 0.084 ;
    END
  END d[295]
  PIN d[296]
    DIRECTION INPUT ;
    USE SIGNAL ;
    PORT
      LAYER M5 ;
        RECT  32.4 0 32.424 0.084 ;
    END
  END d[296]
  PIN d[297]
    DIRECTION INPUT ;
    USE SIGNAL ;
    PORT
      LAYER M5 ;
        RECT  32.304 0 32.328 0.084 ;
    END
  END d[297]
  PIN d[298]
    DIRECTION INPUT ;
    USE SIGNAL ;
    PORT
      LAYER M5 ;
        RECT  32.496 0 32.52 0.084 ;
    END
  END d[298]
  PIN d[299]
    DIRECTION INPUT ;
    USE SIGNAL ;
    PORT
      LAYER M5 ;
        RECT  32.592 0 32.616 0.084 ;
    END
  END d[299]
  PIN d[29]
    DIRECTION INPUT ;
    USE SIGNAL ;
    PORT
      LAYER M5 ;
        RECT  6.576 0 6.6 0.084 ;
    END
  END d[29]
  PIN d[2]
    DIRECTION INPUT ;
    USE SIGNAL ;
    PORT
      LAYER M5 ;
        RECT  3.888 0 3.912 0.084 ;
    END
  END d[2]
  PIN d[300]
    DIRECTION INPUT ;
    USE SIGNAL ;
    PORT
      LAYER M5 ;
        RECT  32.688 0 32.712 0.084 ;
    END
  END d[300]
  PIN d[301]
    DIRECTION INPUT ;
    USE SIGNAL ;
    PORT
      LAYER M5 ;
        RECT  32.784 0 32.808 0.084 ;
    END
  END d[301]
  PIN d[302]
    DIRECTION INPUT ;
    USE SIGNAL ;
    PORT
      LAYER M5 ;
        RECT  32.88 0 32.904 0.084 ;
    END
  END d[302]
  PIN d[303]
    DIRECTION INPUT ;
    USE SIGNAL ;
    PORT
      LAYER M5 ;
        RECT  32.976 0 33 0.084 ;
    END
  END d[303]
  PIN d[304]
    DIRECTION INPUT ;
    USE SIGNAL ;
    PORT
      LAYER M5 ;
        RECT  33.072 0 33.096 0.084 ;
    END
  END d[304]
  PIN d[305]
    DIRECTION INPUT ;
    USE SIGNAL ;
    PORT
      LAYER M5 ;
        RECT  33.168 0 33.192 0.084 ;
    END
  END d[305]
  PIN d[306]
    DIRECTION INPUT ;
    USE SIGNAL ;
    PORT
      LAYER M5 ;
        RECT  33.264 0 33.288 0.084 ;
    END
  END d[306]
  PIN d[307]
    DIRECTION INPUT ;
    USE SIGNAL ;
    PORT
      LAYER M5 ;
        RECT  33.36 0 33.384 0.084 ;
    END
  END d[307]
  PIN d[308]
    DIRECTION INPUT ;
    USE SIGNAL ;
    PORT
      LAYER M5 ;
        RECT  33.456 0 33.48 0.084 ;
    END
  END d[308]
  PIN d[309]
    DIRECTION INPUT ;
    USE SIGNAL ;
    PORT
      LAYER M5 ;
        RECT  33.552 0 33.576 0.084 ;
    END
  END d[309]
  PIN d[30]
    DIRECTION INPUT ;
    USE SIGNAL ;
    PORT
      LAYER M5 ;
        RECT  6.384 0 6.408 0.084 ;
    END
  END d[30]
  PIN d[310]
    DIRECTION INPUT ;
    USE SIGNAL ;
    PORT
      LAYER M5 ;
        RECT  33.648 0 33.672 0.084 ;
    END
  END d[310]
  PIN d[311]
    DIRECTION INPUT ;
    USE SIGNAL ;
    PORT
      LAYER M5 ;
        RECT  33.744 0 33.768 0.084 ;
    END
  END d[311]
  PIN d[312]
    DIRECTION INPUT ;
    USE SIGNAL ;
    PORT
      LAYER M5 ;
        RECT  33.84 0 33.864 0.084 ;
    END
  END d[312]
  PIN d[313]
    DIRECTION INPUT ;
    USE SIGNAL ;
    PORT
      LAYER M5 ;
        RECT  33.936 0 33.96 0.084 ;
    END
  END d[313]
  PIN d[314]
    DIRECTION INPUT ;
    USE SIGNAL ;
    PORT
      LAYER M5 ;
        RECT  34.032 0 34.056 0.084 ;
    END
  END d[314]
  PIN d[315]
    DIRECTION INPUT ;
    USE SIGNAL ;
    PORT
      LAYER M5 ;
        RECT  34.128 0 34.152 0.084 ;
    END
  END d[315]
  PIN d[316]
    DIRECTION INPUT ;
    USE SIGNAL ;
    PORT
      LAYER M5 ;
        RECT  34.224 0 34.248 0.084 ;
    END
  END d[316]
  PIN d[317]
    DIRECTION INPUT ;
    USE SIGNAL ;
    PORT
      LAYER M5 ;
        RECT  34.416 0 34.44 0.084 ;
    END
  END d[317]
  PIN d[318]
    DIRECTION INPUT ;
    USE SIGNAL ;
    PORT
      LAYER M5 ;
        RECT  34.32 0 34.344 0.084 ;
    END
  END d[318]
  PIN d[319]
    DIRECTION INPUT ;
    USE SIGNAL ;
    PORT
      LAYER M5 ;
        RECT  34.512 0 34.536 0.084 ;
    END
  END d[319]
  PIN d[31]
    DIRECTION INPUT ;
    USE SIGNAL ;
    PORT
      LAYER M5 ;
        RECT  6.672 0 6.696 0.084 ;
    END
  END d[31]
  PIN d[320]
    DIRECTION INPUT ;
    USE SIGNAL ;
    PORT
      LAYER M5 ;
        RECT  34.608 0 34.632 0.084 ;
    END
  END d[320]
  PIN d[321]
    DIRECTION INPUT ;
    USE SIGNAL ;
    PORT
      LAYER M5 ;
        RECT  34.8 0 34.824 0.084 ;
    END
  END d[321]
  PIN d[322]
    DIRECTION INPUT ;
    USE SIGNAL ;
    PORT
      LAYER M5 ;
        RECT  34.704 0 34.728 0.084 ;
    END
  END d[322]
  PIN d[323]
    DIRECTION INPUT ;
    USE SIGNAL ;
    PORT
      LAYER M5 ;
        RECT  34.992 0 35.016 0.084 ;
    END
  END d[323]
  PIN d[324]
    DIRECTION INPUT ;
    USE SIGNAL ;
    PORT
      LAYER M5 ;
        RECT  34.896 0 34.92 0.084 ;
    END
  END d[324]
  PIN d[325]
    DIRECTION INPUT ;
    USE SIGNAL ;
    PORT
      LAYER M5 ;
        RECT  35.184 0 35.208 0.084 ;
    END
  END d[325]
  PIN d[326]
    DIRECTION INPUT ;
    USE SIGNAL ;
    PORT
      LAYER M5 ;
        RECT  35.088 0 35.112 0.084 ;
    END
  END d[326]
  PIN d[327]
    DIRECTION INPUT ;
    USE SIGNAL ;
    PORT
      LAYER M5 ;
        RECT  35.376 0 35.4 0.084 ;
    END
  END d[327]
  PIN d[328]
    DIRECTION INPUT ;
    USE SIGNAL ;
    PORT
      LAYER M5 ;
        RECT  35.28 0 35.304 0.084 ;
    END
  END d[328]
  PIN d[329]
    DIRECTION INPUT ;
    USE SIGNAL ;
    PORT
      LAYER M5 ;
        RECT  35.568 0 35.592 0.084 ;
    END
  END d[329]
  PIN d[32]
    DIRECTION INPUT ;
    USE SIGNAL ;
    PORT
      LAYER M5 ;
        RECT  6.864 0 6.888 0.084 ;
    END
  END d[32]
  PIN d[330]
    DIRECTION INPUT ;
    USE SIGNAL ;
    PORT
      LAYER M5 ;
        RECT  35.472 0 35.496 0.084 ;
    END
  END d[330]
  PIN d[331]
    DIRECTION INPUT ;
    USE SIGNAL ;
    PORT
      LAYER M5 ;
        RECT  35.76 0 35.784 0.084 ;
    END
  END d[331]
  PIN d[332]
    DIRECTION INPUT ;
    USE SIGNAL ;
    PORT
      LAYER M5 ;
        RECT  35.664 0 35.688 0.084 ;
    END
  END d[332]
  PIN d[333]
    DIRECTION INPUT ;
    USE SIGNAL ;
    PORT
      LAYER M5 ;
        RECT  35.856 0 35.88 0.084 ;
    END
  END d[333]
  PIN d[334]
    DIRECTION INPUT ;
    USE SIGNAL ;
    PORT
      LAYER M5 ;
        RECT  36.048 0 36.072 0.084 ;
    END
  END d[334]
  PIN d[335]
    DIRECTION INPUT ;
    USE SIGNAL ;
    PORT
      LAYER M5 ;
        RECT  35.952 0 35.976 0.084 ;
    END
  END d[335]
  PIN d[336]
    DIRECTION INPUT ;
    USE SIGNAL ;
    PORT
      LAYER M5 ;
        RECT  36.24 0 36.264 0.084 ;
    END
  END d[336]
  PIN d[337]
    DIRECTION INPUT ;
    USE SIGNAL ;
    PORT
      LAYER M5 ;
        RECT  36.144 0 36.168 0.084 ;
    END
  END d[337]
  PIN d[338]
    DIRECTION INPUT ;
    USE SIGNAL ;
    PORT
      LAYER M5 ;
        RECT  36.432 0 36.456 0.084 ;
    END
  END d[338]
  PIN d[339]
    DIRECTION INPUT ;
    USE SIGNAL ;
    PORT
      LAYER M5 ;
        RECT  36.336 0 36.36 0.084 ;
    END
  END d[339]
  PIN d[33]
    DIRECTION INPUT ;
    USE SIGNAL ;
    PORT
      LAYER M5 ;
        RECT  6.768 0 6.792 0.084 ;
    END
  END d[33]
  PIN d[340]
    DIRECTION INPUT ;
    USE SIGNAL ;
    PORT
      LAYER M5 ;
        RECT  36.624 0 36.648 0.084 ;
    END
  END d[340]
  PIN d[341]
    DIRECTION INPUT ;
    USE SIGNAL ;
    PORT
      LAYER M5 ;
        RECT  36.528 0 36.552 0.084 ;
    END
  END d[341]
  PIN d[342]
    DIRECTION INPUT ;
    USE SIGNAL ;
    PORT
      LAYER M5 ;
        RECT  36.816 0 36.84 0.084 ;
    END
  END d[342]
  PIN d[343]
    DIRECTION INPUT ;
    USE SIGNAL ;
    PORT
      LAYER M5 ;
        RECT  36.72 0 36.744 0.084 ;
    END
  END d[343]
  PIN d[344]
    DIRECTION INPUT ;
    USE SIGNAL ;
    PORT
      LAYER M5 ;
        RECT  36.912 0 36.936 0.084 ;
    END
  END d[344]
  PIN d[345]
    DIRECTION INPUT ;
    USE SIGNAL ;
    PORT
      LAYER M5 ;
        RECT  37.008 0 37.032 0.084 ;
    END
  END d[345]
  PIN d[346]
    DIRECTION INPUT ;
    USE SIGNAL ;
    PORT
      LAYER M5 ;
        RECT  37.2 0 37.224 0.084 ;
    END
  END d[346]
  PIN d[347]
    DIRECTION INPUT ;
    USE SIGNAL ;
    PORT
      LAYER M5 ;
        RECT  37.104 0 37.128 0.084 ;
    END
  END d[347]
  PIN d[348]
    DIRECTION INPUT ;
    USE SIGNAL ;
    PORT
      LAYER M5 ;
        RECT  37.296 0 37.32 0.084 ;
    END
  END d[348]
  PIN d[349]
    DIRECTION INPUT ;
    USE SIGNAL ;
    PORT
      LAYER M5 ;
        RECT  37.392 0 37.416 0.084 ;
    END
  END d[349]
  PIN d[34]
    DIRECTION INPUT ;
    USE SIGNAL ;
    PORT
      LAYER M5 ;
        RECT  7.056 0 7.08 0.084 ;
    END
  END d[34]
  PIN d[350]
    DIRECTION INPUT ;
    USE SIGNAL ;
    PORT
      LAYER M5 ;
        RECT  37.488 0 37.512 0.084 ;
    END
  END d[350]
  PIN d[351]
    DIRECTION INPUT ;
    USE SIGNAL ;
    PORT
      LAYER M5 ;
        RECT  37.584 0 37.608 0.084 ;
    END
  END d[351]
  PIN d[352]
    DIRECTION INPUT ;
    USE SIGNAL ;
    PORT
      LAYER M5 ;
        RECT  37.68 0 37.704 0.084 ;
    END
  END d[352]
  PIN d[353]
    DIRECTION INPUT ;
    USE SIGNAL ;
    PORT
      LAYER M5 ;
        RECT  37.776 0 37.8 0.084 ;
    END
  END d[353]
  PIN d[354]
    DIRECTION INPUT ;
    USE SIGNAL ;
    PORT
      LAYER M5 ;
        RECT  37.872 0 37.896 0.084 ;
    END
  END d[354]
  PIN d[355]
    DIRECTION INPUT ;
    USE SIGNAL ;
    PORT
      LAYER M5 ;
        RECT  37.968 0 37.992 0.084 ;
    END
  END d[355]
  PIN d[356]
    DIRECTION INPUT ;
    USE SIGNAL ;
    PORT
      LAYER M5 ;
        RECT  38.064 0 38.088 0.084 ;
    END
  END d[356]
  PIN d[357]
    DIRECTION INPUT ;
    USE SIGNAL ;
    PORT
      LAYER M5 ;
        RECT  38.16 0 38.184 0.084 ;
    END
  END d[357]
  PIN d[358]
    DIRECTION INPUT ;
    USE SIGNAL ;
    PORT
      LAYER M5 ;
        RECT  38.256 0 38.28 0.084 ;
    END
  END d[358]
  PIN d[359]
    DIRECTION INPUT ;
    USE SIGNAL ;
    PORT
      LAYER M5 ;
        RECT  38.352 0 38.376 0.084 ;
    END
  END d[359]
  PIN d[35]
    DIRECTION INPUT ;
    USE SIGNAL ;
    PORT
      LAYER M5 ;
        RECT  6.96 0 6.984 0.084 ;
    END
  END d[35]
  PIN d[360]
    DIRECTION INPUT ;
    USE SIGNAL ;
    PORT
      LAYER M5 ;
        RECT  38.448 0 38.472 0.084 ;
    END
  END d[360]
  PIN d[361]
    DIRECTION INPUT ;
    USE SIGNAL ;
    PORT
      LAYER M5 ;
        RECT  38.544 0 38.568 0.084 ;
    END
  END d[361]
  PIN d[362]
    DIRECTION INPUT ;
    USE SIGNAL ;
    PORT
      LAYER M5 ;
        RECT  38.64 0 38.664 0.084 ;
    END
  END d[362]
  PIN d[363]
    DIRECTION INPUT ;
    USE SIGNAL ;
    PORT
      LAYER M5 ;
        RECT  38.736 0 38.76 0.084 ;
    END
  END d[363]
  PIN d[364]
    DIRECTION INPUT ;
    USE SIGNAL ;
    PORT
      LAYER M5 ;
        RECT  38.832 0 38.856 0.084 ;
    END
  END d[364]
  PIN d[365]
    DIRECTION INPUT ;
    USE SIGNAL ;
    PORT
      LAYER M5 ;
        RECT  39.024 0 39.048 0.084 ;
    END
  END d[365]
  PIN d[366]
    DIRECTION INPUT ;
    USE SIGNAL ;
    PORT
      LAYER M5 ;
        RECT  38.928 0 38.952 0.084 ;
    END
  END d[366]
  PIN d[367]
    DIRECTION INPUT ;
    USE SIGNAL ;
    PORT
      LAYER M5 ;
        RECT  39.216 0 39.24 0.084 ;
    END
  END d[367]
  PIN d[368]
    DIRECTION INPUT ;
    USE SIGNAL ;
    PORT
      LAYER M5 ;
        RECT  39.12 0 39.144 0.084 ;
    END
  END d[368]
  PIN d[369]
    DIRECTION INPUT ;
    USE SIGNAL ;
    PORT
      LAYER M5 ;
        RECT  39.408 0 39.432 0.084 ;
    END
  END d[369]
  PIN d[36]
    DIRECTION INPUT ;
    USE SIGNAL ;
    PORT
      LAYER M5 ;
        RECT  7.248 0 7.272 0.084 ;
    END
  END d[36]
  PIN d[370]
    DIRECTION INPUT ;
    USE SIGNAL ;
    PORT
      LAYER M5 ;
        RECT  39.312 0 39.336 0.084 ;
    END
  END d[370]
  PIN d[371]
    DIRECTION INPUT ;
    USE SIGNAL ;
    PORT
      LAYER M5 ;
        RECT  39.6 0 39.624 0.084 ;
    END
  END d[371]
  PIN d[372]
    DIRECTION INPUT ;
    USE SIGNAL ;
    PORT
      LAYER M5 ;
        RECT  39.504 0 39.528 0.084 ;
    END
  END d[372]
  PIN d[373]
    DIRECTION INPUT ;
    USE SIGNAL ;
    PORT
      LAYER M5 ;
        RECT  39.792 0 39.816 0.084 ;
    END
  END d[373]
  PIN d[374]
    DIRECTION INPUT ;
    USE SIGNAL ;
    PORT
      LAYER M5 ;
        RECT  39.696 0 39.72 0.084 ;
    END
  END d[374]
  PIN d[375]
    DIRECTION INPUT ;
    USE SIGNAL ;
    PORT
      LAYER M5 ;
        RECT  39.984 0 40.008 0.084 ;
    END
  END d[375]
  PIN d[376]
    DIRECTION INPUT ;
    USE SIGNAL ;
    PORT
      LAYER M5 ;
        RECT  39.888 0 39.912 0.084 ;
    END
  END d[376]
  PIN d[377]
    DIRECTION INPUT ;
    USE SIGNAL ;
    PORT
      LAYER M5 ;
        RECT  40.176 0 40.2 0.084 ;
    END
  END d[377]
  PIN d[378]
    DIRECTION INPUT ;
    USE SIGNAL ;
    PORT
      LAYER M5 ;
        RECT  40.08 0 40.104 0.084 ;
    END
  END d[378]
  PIN d[379]
    DIRECTION INPUT ;
    USE SIGNAL ;
    PORT
      LAYER M5 ;
        RECT  40.368 0 40.392 0.084 ;
    END
  END d[379]
  PIN d[37]
    DIRECTION INPUT ;
    USE SIGNAL ;
    PORT
      LAYER M5 ;
        RECT  7.152 0 7.176 0.084 ;
    END
  END d[37]
  PIN d[380]
    DIRECTION INPUT ;
    USE SIGNAL ;
    PORT
      LAYER M5 ;
        RECT  40.272 0 40.296 0.084 ;
    END
  END d[380]
  PIN d[381]
    DIRECTION INPUT ;
    USE SIGNAL ;
    PORT
      LAYER M5 ;
        RECT  40.56 0 40.584 0.084 ;
    END
  END d[381]
  PIN d[382]
    DIRECTION INPUT ;
    USE SIGNAL ;
    PORT
      LAYER M5 ;
        RECT  40.464 0 40.488 0.084 ;
    END
  END d[382]
  PIN d[383]
    DIRECTION INPUT ;
    USE SIGNAL ;
    PORT
      LAYER M5 ;
        RECT  40.656 0 40.68 0.084 ;
    END
  END d[383]
  PIN d[384]
    DIRECTION INPUT ;
    USE SIGNAL ;
    PORT
      LAYER M5 ;
        RECT  40.848 0 40.872 0.084 ;
    END
  END d[384]
  PIN d[385]
    DIRECTION INPUT ;
    USE SIGNAL ;
    PORT
      LAYER M5 ;
        RECT  40.752 0 40.776 0.084 ;
    END
  END d[385]
  PIN d[386]
    DIRECTION INPUT ;
    USE SIGNAL ;
    PORT
      LAYER M5 ;
        RECT  41.04 0 41.064 0.084 ;
    END
  END d[386]
  PIN d[387]
    DIRECTION INPUT ;
    USE SIGNAL ;
    PORT
      LAYER M5 ;
        RECT  40.944 0 40.968 0.084 ;
    END
  END d[387]
  PIN d[388]
    DIRECTION INPUT ;
    USE SIGNAL ;
    PORT
      LAYER M5 ;
        RECT  41.232 0 41.256 0.084 ;
    END
  END d[388]
  PIN d[389]
    DIRECTION INPUT ;
    USE SIGNAL ;
    PORT
      LAYER M5 ;
        RECT  41.136 0 41.16 0.084 ;
    END
  END d[389]
  PIN d[38]
    DIRECTION INPUT ;
    USE SIGNAL ;
    PORT
      LAYER M5 ;
        RECT  7.44 0 7.464 0.084 ;
    END
  END d[38]
  PIN d[390]
    DIRECTION INPUT ;
    USE SIGNAL ;
    PORT
      LAYER M5 ;
        RECT  41.424 0 41.448 0.084 ;
    END
  END d[390]
  PIN d[391]
    DIRECTION INPUT ;
    USE SIGNAL ;
    PORT
      LAYER M5 ;
        RECT  41.328 0 41.352 0.084 ;
    END
  END d[391]
  PIN d[392]
    DIRECTION INPUT ;
    USE SIGNAL ;
    PORT
      LAYER M5 ;
        RECT  41.712 0 41.736 0.084 ;
    END
  END d[392]
  PIN d[393]
    DIRECTION INPUT ;
    USE SIGNAL ;
    PORT
      LAYER M5 ;
        RECT  41.52 0 41.544 0.084 ;
    END
  END d[393]
  PIN d[394]
    DIRECTION INPUT ;
    USE SIGNAL ;
    PORT
      LAYER M5 ;
        RECT  41.808 0 41.832 0.084 ;
    END
  END d[394]
  PIN d[395]
    DIRECTION INPUT ;
    USE SIGNAL ;
    PORT
      LAYER M5 ;
        RECT  41.616 0 41.64 0.084 ;
    END
  END d[395]
  PIN d[396]
    DIRECTION INPUT ;
    USE SIGNAL ;
    PORT
      LAYER M5 ;
        RECT  42 0 42.024 0.084 ;
    END
  END d[396]
  PIN d[397]
    DIRECTION INPUT ;
    USE SIGNAL ;
    PORT
      LAYER M5 ;
        RECT  41.904 0 41.928 0.084 ;
    END
  END d[397]
  PIN d[398]
    DIRECTION INPUT ;
    USE SIGNAL ;
    PORT
      LAYER M5 ;
        RECT  42.192 0 42.216 0.084 ;
    END
  END d[398]
  PIN d[399]
    DIRECTION INPUT ;
    USE SIGNAL ;
    PORT
      LAYER M5 ;
        RECT  42.096 0 42.12 0.084 ;
    END
  END d[399]
  PIN d[39]
    DIRECTION INPUT ;
    USE SIGNAL ;
    PORT
      LAYER M5 ;
        RECT  7.344 0 7.368 0.084 ;
    END
  END d[39]
  PIN d[3]
    DIRECTION INPUT ;
    USE SIGNAL ;
    PORT
      LAYER M5 ;
        RECT  3.984 0 4.008 0.084 ;
    END
  END d[3]
  PIN d[400]
    DIRECTION INPUT ;
    USE SIGNAL ;
    PORT
      LAYER M5 ;
        RECT  42.288 0 42.312 0.084 ;
    END
  END d[400]
  PIN d[401]
    DIRECTION INPUT ;
    USE SIGNAL ;
    PORT
      LAYER M5 ;
        RECT  42.384 0 42.408 0.084 ;
    END
  END d[401]
  PIN d[402]
    DIRECTION INPUT ;
    USE SIGNAL ;
    PORT
      LAYER M5 ;
        RECT  42.48 0 42.504 0.084 ;
    END
  END d[402]
  PIN d[403]
    DIRECTION INPUT ;
    USE SIGNAL ;
    PORT
      LAYER M5 ;
        RECT  42.576 0 42.6 0.084 ;
    END
  END d[403]
  PIN d[404]
    DIRECTION INPUT ;
    USE SIGNAL ;
    PORT
      LAYER M5 ;
        RECT  42.672 0 42.696 0.084 ;
    END
  END d[404]
  PIN d[405]
    DIRECTION INPUT ;
    USE SIGNAL ;
    PORT
      LAYER M5 ;
        RECT  42.768 0 42.792 0.084 ;
    END
  END d[405]
  PIN d[406]
    DIRECTION INPUT ;
    USE SIGNAL ;
    PORT
      LAYER M5 ;
        RECT  42.864 0 42.888 0.084 ;
    END
  END d[406]
  PIN d[407]
    DIRECTION INPUT ;
    USE SIGNAL ;
    PORT
      LAYER M5 ;
        RECT  42.96 0 42.984 0.084 ;
    END
  END d[407]
  PIN d[408]
    DIRECTION INPUT ;
    USE SIGNAL ;
    PORT
      LAYER M5 ;
        RECT  43.056 0 43.08 0.084 ;
    END
  END d[408]
  PIN d[409]
    DIRECTION INPUT ;
    USE SIGNAL ;
    PORT
      LAYER M5 ;
        RECT  43.152 0 43.176 0.084 ;
    END
  END d[409]
  PIN d[40]
    DIRECTION INPUT ;
    USE SIGNAL ;
    PORT
      LAYER M5 ;
        RECT  7.632 0 7.656 0.084 ;
    END
  END d[40]
  PIN d[410]
    DIRECTION INPUT ;
    USE SIGNAL ;
    PORT
      LAYER M5 ;
        RECT  43.248 0 43.272 0.084 ;
    END
  END d[410]
  PIN d[411]
    DIRECTION INPUT ;
    USE SIGNAL ;
    PORT
      LAYER M5 ;
        RECT  43.344 0 43.368 0.084 ;
    END
  END d[411]
  PIN d[412]
    DIRECTION INPUT ;
    USE SIGNAL ;
    PORT
      LAYER M5 ;
        RECT  43.44 0 43.464 0.084 ;
    END
  END d[412]
  PIN d[413]
    DIRECTION INPUT ;
    USE SIGNAL ;
    PORT
      LAYER M5 ;
        RECT  43.536 0 43.56 0.084 ;
    END
  END d[413]
  PIN d[414]
    DIRECTION INPUT ;
    USE SIGNAL ;
    PORT
      LAYER M5 ;
        RECT  43.632 0 43.656 0.084 ;
    END
  END d[414]
  PIN d[415]
    DIRECTION INPUT ;
    USE SIGNAL ;
    PORT
      LAYER M5 ;
        RECT  43.824 0 43.848 0.084 ;
    END
  END d[415]
  PIN d[416]
    DIRECTION INPUT ;
    USE SIGNAL ;
    PORT
      LAYER M5 ;
        RECT  43.728 0 43.752 0.084 ;
    END
  END d[416]
  PIN d[417]
    DIRECTION INPUT ;
    USE SIGNAL ;
    PORT
      LAYER M5 ;
        RECT  44.016 0 44.04 0.084 ;
    END
  END d[417]
  PIN d[418]
    DIRECTION INPUT ;
    USE SIGNAL ;
    PORT
      LAYER M5 ;
        RECT  43.92 0 43.944 0.084 ;
    END
  END d[418]
  PIN d[419]
    DIRECTION INPUT ;
    USE SIGNAL ;
    PORT
      LAYER M5 ;
        RECT  44.208 0 44.232 0.084 ;
    END
  END d[419]
  PIN d[41]
    DIRECTION INPUT ;
    USE SIGNAL ;
    PORT
      LAYER M5 ;
        RECT  7.536 0 7.56 0.084 ;
    END
  END d[41]
  PIN d[420]
    DIRECTION INPUT ;
    USE SIGNAL ;
    PORT
      LAYER M5 ;
        RECT  44.112 0 44.136 0.084 ;
    END
  END d[420]
  PIN d[421]
    DIRECTION INPUT ;
    USE SIGNAL ;
    PORT
      LAYER M5 ;
        RECT  44.4 0 44.424 0.084 ;
    END
  END d[421]
  PIN d[422]
    DIRECTION INPUT ;
    USE SIGNAL ;
    PORT
      LAYER M5 ;
        RECT  44.304 0 44.328 0.084 ;
    END
  END d[422]
  PIN d[423]
    DIRECTION INPUT ;
    USE SIGNAL ;
    PORT
      LAYER M5 ;
        RECT  44.592 0 44.616 0.084 ;
    END
  END d[423]
  PIN d[424]
    DIRECTION INPUT ;
    USE SIGNAL ;
    PORT
      LAYER M5 ;
        RECT  44.496 0 44.52 0.084 ;
    END
  END d[424]
  PIN d[425]
    DIRECTION INPUT ;
    USE SIGNAL ;
    PORT
      LAYER M5 ;
        RECT  44.784 0 44.808 0.084 ;
    END
  END d[425]
  PIN d[426]
    DIRECTION INPUT ;
    USE SIGNAL ;
    PORT
      LAYER M5 ;
        RECT  44.688 0 44.712 0.084 ;
    END
  END d[426]
  PIN d[427]
    DIRECTION INPUT ;
    USE SIGNAL ;
    PORT
      LAYER M5 ;
        RECT  44.976 0 45 0.084 ;
    END
  END d[427]
  PIN d[428]
    DIRECTION INPUT ;
    USE SIGNAL ;
    PORT
      LAYER M5 ;
        RECT  44.88 0 44.904 0.084 ;
    END
  END d[428]
  PIN d[429]
    DIRECTION INPUT ;
    USE SIGNAL ;
    PORT
      LAYER M5 ;
        RECT  45.168 0 45.192 0.084 ;
    END
  END d[429]
  PIN d[42]
    DIRECTION INPUT ;
    USE SIGNAL ;
    PORT
      LAYER M5 ;
        RECT  7.728 0 7.752 0.084 ;
    END
  END d[42]
  PIN d[430]
    DIRECTION INPUT ;
    USE SIGNAL ;
    PORT
      LAYER M5 ;
        RECT  45.072 0 45.096 0.084 ;
    END
  END d[430]
  PIN d[431]
    DIRECTION INPUT ;
    USE SIGNAL ;
    PORT
      LAYER M5 ;
        RECT  45.36 0 45.384 0.084 ;
    END
  END d[431]
  PIN d[432]
    DIRECTION INPUT ;
    USE SIGNAL ;
    PORT
      LAYER M5 ;
        RECT  45.264 0 45.288 0.084 ;
    END
  END d[432]
  PIN d[433]
    DIRECTION INPUT ;
    USE SIGNAL ;
    PORT
      LAYER M5 ;
        RECT  45.456 0 45.48 0.084 ;
    END
  END d[433]
  PIN d[434]
    DIRECTION INPUT ;
    USE SIGNAL ;
    PORT
      LAYER M5 ;
        RECT  45.648 0 45.672 0.084 ;
    END
  END d[434]
  PIN d[435]
    DIRECTION INPUT ;
    USE SIGNAL ;
    PORT
      LAYER M5 ;
        RECT  45.552 0 45.576 0.084 ;
    END
  END d[435]
  PIN d[436]
    DIRECTION INPUT ;
    USE SIGNAL ;
    PORT
      LAYER M5 ;
        RECT  45.84 0 45.864 0.084 ;
    END
  END d[436]
  PIN d[437]
    DIRECTION INPUT ;
    USE SIGNAL ;
    PORT
      LAYER M5 ;
        RECT  45.744 0 45.768 0.084 ;
    END
  END d[437]
  PIN d[438]
    DIRECTION INPUT ;
    USE SIGNAL ;
    PORT
      LAYER M5 ;
        RECT  46.032 0 46.056 0.084 ;
    END
  END d[438]
  PIN d[439]
    DIRECTION INPUT ;
    USE SIGNAL ;
    PORT
      LAYER M5 ;
        RECT  45.936 0 45.96 0.084 ;
    END
  END d[439]
  PIN d[43]
    DIRECTION INPUT ;
    USE SIGNAL ;
    PORT
      LAYER M5 ;
        RECT  7.824 0 7.848 0.084 ;
    END
  END d[43]
  PIN d[440]
    DIRECTION INPUT ;
    USE SIGNAL ;
    PORT
      LAYER M5 ;
        RECT  46.224 0 46.248 0.084 ;
    END
  END d[440]
  PIN d[441]
    DIRECTION INPUT ;
    USE SIGNAL ;
    PORT
      LAYER M5 ;
        RECT  46.128 0 46.152 0.084 ;
    END
  END d[441]
  PIN d[442]
    DIRECTION INPUT ;
    USE SIGNAL ;
    PORT
      LAYER M5 ;
        RECT  46.416 0 46.44 0.084 ;
    END
  END d[442]
  PIN d[443]
    DIRECTION INPUT ;
    USE SIGNAL ;
    PORT
      LAYER M5 ;
        RECT  46.32 0 46.344 0.084 ;
    END
  END d[443]
  PIN d[444]
    DIRECTION INPUT ;
    USE SIGNAL ;
    PORT
      LAYER M5 ;
        RECT  46.608 0 46.632 0.084 ;
    END
  END d[444]
  PIN d[445]
    DIRECTION INPUT ;
    USE SIGNAL ;
    PORT
      LAYER M5 ;
        RECT  46.512 0 46.536 0.084 ;
    END
  END d[445]
  PIN d[446]
    DIRECTION INPUT ;
    USE SIGNAL ;
    PORT
      LAYER M5 ;
        RECT  46.8 0 46.824 0.084 ;
    END
  END d[446]
  PIN d[447]
    DIRECTION INPUT ;
    USE SIGNAL ;
    PORT
      LAYER M5 ;
        RECT  46.704 0 46.728 0.084 ;
    END
  END d[447]
  PIN d[448]
    DIRECTION INPUT ;
    USE SIGNAL ;
    PORT
      LAYER M5 ;
        RECT  46.896 0 46.92 0.084 ;
    END
  END d[448]
  PIN d[449]
    DIRECTION INPUT ;
    USE SIGNAL ;
    PORT
      LAYER M5 ;
        RECT  46.992 0 47.016 0.084 ;
    END
  END d[449]
  PIN d[44]
    DIRECTION INPUT ;
    USE SIGNAL ;
    PORT
      LAYER M5 ;
        RECT  7.92 0 7.944 0.084 ;
    END
  END d[44]
  PIN d[450]
    DIRECTION INPUT ;
    USE SIGNAL ;
    PORT
      LAYER M5 ;
        RECT  47.088 0 47.112 0.084 ;
    END
  END d[450]
  PIN d[451]
    DIRECTION INPUT ;
    USE SIGNAL ;
    PORT
      LAYER M5 ;
        RECT  47.184 0 47.208 0.084 ;
    END
  END d[451]
  PIN d[452]
    DIRECTION INPUT ;
    USE SIGNAL ;
    PORT
      LAYER M5 ;
        RECT  47.28 0 47.304 0.084 ;
    END
  END d[452]
  PIN d[453]
    DIRECTION INPUT ;
    USE SIGNAL ;
    PORT
      LAYER M5 ;
        RECT  47.376 0 47.4 0.084 ;
    END
  END d[453]
  PIN d[454]
    DIRECTION INPUT ;
    USE SIGNAL ;
    PORT
      LAYER M5 ;
        RECT  47.472 0 47.496 0.084 ;
    END
  END d[454]
  PIN d[455]
    DIRECTION INPUT ;
    USE SIGNAL ;
    PORT
      LAYER M5 ;
        RECT  47.568 0 47.592 0.084 ;
    END
  END d[455]
  PIN d[456]
    DIRECTION INPUT ;
    USE SIGNAL ;
    PORT
      LAYER M5 ;
        RECT  47.664 0 47.688 0.084 ;
    END
  END d[456]
  PIN d[45]
    DIRECTION INPUT ;
    USE SIGNAL ;
    PORT
      LAYER M5 ;
        RECT  8.016 0 8.04 0.084 ;
    END
  END d[45]
  PIN d[46]
    DIRECTION INPUT ;
    USE SIGNAL ;
    PORT
      LAYER M5 ;
        RECT  8.112 0 8.136 0.084 ;
    END
  END d[46]
  PIN d[47]
    DIRECTION INPUT ;
    USE SIGNAL ;
    PORT
      LAYER M5 ;
        RECT  8.208 0 8.232 0.084 ;
    END
  END d[47]
  PIN d[48]
    DIRECTION INPUT ;
    USE SIGNAL ;
    PORT
      LAYER M5 ;
        RECT  8.304 0 8.328 0.084 ;
    END
  END d[48]
  PIN d[49]
    DIRECTION INPUT ;
    USE SIGNAL ;
    PORT
      LAYER M5 ;
        RECT  8.4 0 8.424 0.084 ;
    END
  END d[49]
  PIN d[4]
    DIRECTION INPUT ;
    USE SIGNAL ;
    PORT
      LAYER M5 ;
        RECT  4.08 0 4.104 0.084 ;
    END
  END d[4]
  PIN d[50]
    DIRECTION INPUT ;
    USE SIGNAL ;
    PORT
      LAYER M5 ;
        RECT  8.496 0 8.52 0.084 ;
    END
  END d[50]
  PIN d[51]
    DIRECTION INPUT ;
    USE SIGNAL ;
    PORT
      LAYER M5 ;
        RECT  8.592 0 8.616 0.084 ;
    END
  END d[51]
  PIN d[52]
    DIRECTION INPUT ;
    USE SIGNAL ;
    PORT
      LAYER M5 ;
        RECT  8.688 0 8.712 0.084 ;
    END
  END d[52]
  PIN d[53]
    DIRECTION INPUT ;
    USE SIGNAL ;
    PORT
      LAYER M5 ;
        RECT  8.784 0 8.808 0.084 ;
    END
  END d[53]
  PIN d[54]
    DIRECTION INPUT ;
    USE SIGNAL ;
    PORT
      LAYER M5 ;
        RECT  8.88 0 8.904 0.084 ;
    END
  END d[54]
  PIN d[55]
    DIRECTION INPUT ;
    USE SIGNAL ;
    PORT
      LAYER M5 ;
        RECT  8.976 0 9 0.084 ;
    END
  END d[55]
  PIN d[56]
    DIRECTION INPUT ;
    USE SIGNAL ;
    PORT
      LAYER M5 ;
        RECT  9.072 0 9.096 0.084 ;
    END
  END d[56]
  PIN d[57]
    DIRECTION INPUT ;
    USE SIGNAL ;
    PORT
      LAYER M5 ;
        RECT  9.168 0 9.192 0.084 ;
    END
  END d[57]
  PIN d[58]
    DIRECTION INPUT ;
    USE SIGNAL ;
    PORT
      LAYER M5 ;
        RECT  9.264 0 9.288 0.084 ;
    END
  END d[58]
  PIN d[59]
    DIRECTION INPUT ;
    USE SIGNAL ;
    PORT
      LAYER M5 ;
        RECT  9.36 0 9.384 0.084 ;
    END
  END d[59]
  PIN d[5]
    DIRECTION INPUT ;
    USE SIGNAL ;
    PORT
      LAYER M5 ;
        RECT  4.176 0 4.2 0.084 ;
    END
  END d[5]
  PIN d[60]
    DIRECTION INPUT ;
    USE SIGNAL ;
    PORT
      LAYER M5 ;
        RECT  9.456 0 9.48 0.084 ;
    END
  END d[60]
  PIN d[61]
    DIRECTION INPUT ;
    USE SIGNAL ;
    PORT
      LAYER M5 ;
        RECT  9.648 0 9.672 0.084 ;
    END
  END d[61]
  PIN d[62]
    DIRECTION INPUT ;
    USE SIGNAL ;
    PORT
      LAYER M5 ;
        RECT  9.552 0 9.576 0.084 ;
    END
  END d[62]
  PIN d[63]
    DIRECTION INPUT ;
    USE SIGNAL ;
    PORT
      LAYER M5 ;
        RECT  9.84 0 9.864 0.084 ;
    END
  END d[63]
  PIN d[64]
    DIRECTION INPUT ;
    USE SIGNAL ;
    PORT
      LAYER M5 ;
        RECT  9.744 0 9.768 0.084 ;
    END
  END d[64]
  PIN d[65]
    DIRECTION INPUT ;
    USE SIGNAL ;
    PORT
      LAYER M5 ;
        RECT  10.032 0 10.056 0.084 ;
    END
  END d[65]
  PIN d[66]
    DIRECTION INPUT ;
    USE SIGNAL ;
    PORT
      LAYER M5 ;
        RECT  9.936 0 9.96 0.084 ;
    END
  END d[66]
  PIN d[67]
    DIRECTION INPUT ;
    USE SIGNAL ;
    PORT
      LAYER M5 ;
        RECT  10.224 0 10.248 0.084 ;
    END
  END d[67]
  PIN d[68]
    DIRECTION INPUT ;
    USE SIGNAL ;
    PORT
      LAYER M5 ;
        RECT  10.128 0 10.152 0.084 ;
    END
  END d[68]
  PIN d[69]
    DIRECTION INPUT ;
    USE SIGNAL ;
    PORT
      LAYER M5 ;
        RECT  10.416 0 10.44 0.084 ;
    END
  END d[69]
  PIN d[6]
    DIRECTION INPUT ;
    USE SIGNAL ;
    PORT
      LAYER M5 ;
        RECT  4.272 0 4.296 0.084 ;
    END
  END d[6]
  PIN d[70]
    DIRECTION INPUT ;
    USE SIGNAL ;
    PORT
      LAYER M5 ;
        RECT  10.32 0 10.344 0.084 ;
    END
  END d[70]
  PIN d[71]
    DIRECTION INPUT ;
    USE SIGNAL ;
    PORT
      LAYER M5 ;
        RECT  10.608 0 10.632 0.084 ;
    END
  END d[71]
  PIN d[72]
    DIRECTION INPUT ;
    USE SIGNAL ;
    PORT
      LAYER M5 ;
        RECT  10.512 0 10.536 0.084 ;
    END
  END d[72]
  PIN d[73]
    DIRECTION INPUT ;
    USE SIGNAL ;
    PORT
      LAYER M5 ;
        RECT  10.8 0 10.824 0.084 ;
    END
  END d[73]
  PIN d[74]
    DIRECTION INPUT ;
    USE SIGNAL ;
    PORT
      LAYER M5 ;
        RECT  10.704 0 10.728 0.084 ;
    END
  END d[74]
  PIN d[75]
    DIRECTION INPUT ;
    USE SIGNAL ;
    PORT
      LAYER M5 ;
        RECT  11.088 0 11.112 0.084 ;
    END
  END d[75]
  PIN d[76]
    DIRECTION INPUT ;
    USE SIGNAL ;
    PORT
      LAYER M5 ;
        RECT  10.896 0 10.92 0.084 ;
    END
  END d[76]
  PIN d[77]
    DIRECTION INPUT ;
    USE SIGNAL ;
    PORT
      LAYER M5 ;
        RECT  11.28 0 11.304 0.084 ;
    END
  END d[77]
  PIN d[78]
    DIRECTION INPUT ;
    USE SIGNAL ;
    PORT
      LAYER M5 ;
        RECT  10.992 0 11.016 0.084 ;
    END
  END d[78]
  PIN d[79]
    DIRECTION INPUT ;
    USE SIGNAL ;
    PORT
      LAYER M5 ;
        RECT  11.376 0 11.4 0.084 ;
    END
  END d[79]
  PIN d[7]
    DIRECTION INPUT ;
    USE SIGNAL ;
    PORT
      LAYER M5 ;
        RECT  4.368 0 4.392 0.084 ;
    END
  END d[7]
  PIN d[80]
    DIRECTION INPUT ;
    USE SIGNAL ;
    PORT
      LAYER M5 ;
        RECT  11.184 0 11.208 0.084 ;
    END
  END d[80]
  PIN d[81]
    DIRECTION INPUT ;
    USE SIGNAL ;
    PORT
      LAYER M5 ;
        RECT  11.472 0 11.496 0.084 ;
    END
  END d[81]
  PIN d[82]
    DIRECTION INPUT ;
    USE SIGNAL ;
    PORT
      LAYER M5 ;
        RECT  11.664 0 11.688 0.084 ;
    END
  END d[82]
  PIN d[83]
    DIRECTION INPUT ;
    USE SIGNAL ;
    PORT
      LAYER M5 ;
        RECT  11.568 0 11.592 0.084 ;
    END
  END d[83]
  PIN d[84]
    DIRECTION INPUT ;
    USE SIGNAL ;
    PORT
      LAYER M5 ;
        RECT  11.856 0 11.88 0.084 ;
    END
  END d[84]
  PIN d[85]
    DIRECTION INPUT ;
    USE SIGNAL ;
    PORT
      LAYER M5 ;
        RECT  11.76 0 11.784 0.084 ;
    END
  END d[85]
  PIN d[86]
    DIRECTION INPUT ;
    USE SIGNAL ;
    PORT
      LAYER M5 ;
        RECT  12.048 0 12.072 0.084 ;
    END
  END d[86]
  PIN d[87]
    DIRECTION INPUT ;
    USE SIGNAL ;
    PORT
      LAYER M5 ;
        RECT  11.952 0 11.976 0.084 ;
    END
  END d[87]
  PIN d[88]
    DIRECTION INPUT ;
    USE SIGNAL ;
    PORT
      LAYER M5 ;
        RECT  12.24 0 12.264 0.084 ;
    END
  END d[88]
  PIN d[89]
    DIRECTION INPUT ;
    USE SIGNAL ;
    PORT
      LAYER M5 ;
        RECT  12.144 0 12.168 0.084 ;
    END
  END d[89]
  PIN d[8]
    DIRECTION INPUT ;
    USE SIGNAL ;
    PORT
      LAYER M5 ;
        RECT  4.464 0 4.488 0.084 ;
    END
  END d[8]
  PIN d[90]
    DIRECTION INPUT ;
    USE SIGNAL ;
    PORT
      LAYER M5 ;
        RECT  12.432 0 12.456 0.084 ;
    END
  END d[90]
  PIN d[91]
    DIRECTION INPUT ;
    USE SIGNAL ;
    PORT
      LAYER M5 ;
        RECT  12.336 0 12.36 0.084 ;
    END
  END d[91]
  PIN d[92]
    DIRECTION INPUT ;
    USE SIGNAL ;
    PORT
      LAYER M5 ;
        RECT  12.624 0 12.648 0.084 ;
    END
  END d[92]
  PIN d[93]
    DIRECTION INPUT ;
    USE SIGNAL ;
    PORT
      LAYER M5 ;
        RECT  12.528 0 12.552 0.084 ;
    END
  END d[93]
  PIN d[94]
    DIRECTION INPUT ;
    USE SIGNAL ;
    PORT
      LAYER M5 ;
        RECT  12.816 0 12.84 0.084 ;
    END
  END d[94]
  PIN d[95]
    DIRECTION INPUT ;
    USE SIGNAL ;
    PORT
      LAYER M5 ;
        RECT  12.72 0 12.744 0.084 ;
    END
  END d[95]
  PIN d[96]
    DIRECTION INPUT ;
    USE SIGNAL ;
    PORT
      LAYER M5 ;
        RECT  12.912 0 12.936 0.084 ;
    END
  END d[96]
  PIN d[97]
    DIRECTION INPUT ;
    USE SIGNAL ;
    PORT
      LAYER M5 ;
        RECT  13.008 0 13.032 0.084 ;
    END
  END d[97]
  PIN d[98]
    DIRECTION INPUT ;
    USE SIGNAL ;
    PORT
      LAYER M5 ;
        RECT  13.104 0 13.128 0.084 ;
    END
  END d[98]
  PIN d[99]
    DIRECTION INPUT ;
    USE SIGNAL ;
    PORT
      LAYER M5 ;
        RECT  13.2 0 13.224 0.084 ;
    END
  END d[99]
  PIN d[9]
    DIRECTION INPUT ;
    USE SIGNAL ;
    PORT
      LAYER M5 ;
        RECT  4.656 0 4.68 0.084 ;
    END
  END d[9]
  PIN fault
    DIRECTION OUTPUT ;
    USE SIGNAL ;
    PORT
      LAYER M5 ;
        RECT  25.488 78.108 25.512 78.192 ;
    END
  END fault
  PIN fclk
    DIRECTION INPUT ;
    USE SIGNAL ;
    PORT
      LAYER M5 ;
        RECT  25.584 0 25.608 0.084 ;
    END
  END fclk
  PIN q[0]
    DIRECTION OUTPUT ;
    USE SIGNAL ;
    PORT
      LAYER M5 ;
        RECT  3.312 78.108 3.336 78.192 ;
    END
  END q[0]
  PIN q[100]
    DIRECTION OUTPUT ;
    USE SIGNAL ;
    PORT
      LAYER M5 ;
        RECT  12.912 78.108 12.936 78.192 ;
    END
  END q[100]
  PIN q[101]
    DIRECTION OUTPUT ;
    USE SIGNAL ;
    PORT
      LAYER M5 ;
        RECT  13.008 78.108 13.032 78.192 ;
    END
  END q[101]
  PIN q[102]
    DIRECTION OUTPUT ;
    USE SIGNAL ;
    PORT
      LAYER M5 ;
        RECT  13.104 78.108 13.128 78.192 ;
    END
  END q[102]
  PIN q[103]
    DIRECTION OUTPUT ;
    USE SIGNAL ;
    PORT
      LAYER M5 ;
        RECT  13.2 78.108 13.224 78.192 ;
    END
  END q[103]
  PIN q[104]
    DIRECTION OUTPUT ;
    USE SIGNAL ;
    PORT
      LAYER M5 ;
        RECT  13.296 78.108 13.32 78.192 ;
    END
  END q[104]
  PIN q[105]
    DIRECTION OUTPUT ;
    USE SIGNAL ;
    PORT
      LAYER M5 ;
        RECT  13.392 78.108 13.416 78.192 ;
    END
  END q[105]
  PIN q[106]
    DIRECTION OUTPUT ;
    USE SIGNAL ;
    PORT
      LAYER M5 ;
        RECT  13.488 78.108 13.512 78.192 ;
    END
  END q[106]
  PIN q[107]
    DIRECTION OUTPUT ;
    USE SIGNAL ;
    PORT
      LAYER M5 ;
        RECT  13.584 78.108 13.608 78.192 ;
    END
  END q[107]
  PIN q[108]
    DIRECTION OUTPUT ;
    USE SIGNAL ;
    PORT
      LAYER M5 ;
        RECT  13.68 78.108 13.704 78.192 ;
    END
  END q[108]
  PIN q[109]
    DIRECTION OUTPUT ;
    USE SIGNAL ;
    PORT
      LAYER M5 ;
        RECT  13.776 78.108 13.8 78.192 ;
    END
  END q[109]
  PIN q[10]
    DIRECTION OUTPUT ;
    USE SIGNAL ;
    PORT
      LAYER M5 ;
        RECT  4.176 78.108 4.2 78.192 ;
    END
  END q[10]
  PIN q[110]
    DIRECTION OUTPUT ;
    USE SIGNAL ;
    PORT
      LAYER M5 ;
        RECT  13.872 78.108 13.896 78.192 ;
    END
  END q[110]
  PIN q[111]
    DIRECTION OUTPUT ;
    USE SIGNAL ;
    PORT
      LAYER M5 ;
        RECT  14.064 78.108 14.088 78.192 ;
    END
  END q[111]
  PIN q[112]
    DIRECTION OUTPUT ;
    USE SIGNAL ;
    PORT
      LAYER M5 ;
        RECT  13.968 78.108 13.992 78.192 ;
    END
  END q[112]
  PIN q[113]
    DIRECTION OUTPUT ;
    USE SIGNAL ;
    PORT
      LAYER M5 ;
        RECT  14.256 78.108 14.28 78.192 ;
    END
  END q[113]
  PIN q[114]
    DIRECTION OUTPUT ;
    USE SIGNAL ;
    PORT
      LAYER M5 ;
        RECT  14.16 78.108 14.184 78.192 ;
    END
  END q[114]
  PIN q[115]
    DIRECTION OUTPUT ;
    USE SIGNAL ;
    PORT
      LAYER M5 ;
        RECT  14.448 78.108 14.472 78.192 ;
    END
  END q[115]
  PIN q[116]
    DIRECTION OUTPUT ;
    USE SIGNAL ;
    PORT
      LAYER M5 ;
        RECT  14.352 78.108 14.376 78.192 ;
    END
  END q[116]
  PIN q[117]
    DIRECTION OUTPUT ;
    USE SIGNAL ;
    PORT
      LAYER M5 ;
        RECT  14.64 78.108 14.664 78.192 ;
    END
  END q[117]
  PIN q[118]
    DIRECTION OUTPUT ;
    USE SIGNAL ;
    PORT
      LAYER M5 ;
        RECT  14.544 78.108 14.568 78.192 ;
    END
  END q[118]
  PIN q[119]
    DIRECTION OUTPUT ;
    USE SIGNAL ;
    PORT
      LAYER M5 ;
        RECT  14.928 78.108 14.952 78.192 ;
    END
  END q[119]
  PIN q[11]
    DIRECTION OUTPUT ;
    USE SIGNAL ;
    PORT
      LAYER M5 ;
        RECT  4.464 78.108 4.488 78.192 ;
    END
  END q[11]
  PIN q[120]
    DIRECTION OUTPUT ;
    USE SIGNAL ;
    PORT
      LAYER M5 ;
        RECT  14.736 78.108 14.76 78.192 ;
    END
  END q[120]
  PIN q[121]
    DIRECTION OUTPUT ;
    USE SIGNAL ;
    PORT
      LAYER M5 ;
        RECT  15.024 78.108 15.048 78.192 ;
    END
  END q[121]
  PIN q[122]
    DIRECTION OUTPUT ;
    USE SIGNAL ;
    PORT
      LAYER M5 ;
        RECT  14.832 78.108 14.856 78.192 ;
    END
  END q[122]
  PIN q[123]
    DIRECTION OUTPUT ;
    USE SIGNAL ;
    PORT
      LAYER M5 ;
        RECT  15.216 78.108 15.24 78.192 ;
    END
  END q[123]
  PIN q[124]
    DIRECTION OUTPUT ;
    USE SIGNAL ;
    PORT
      LAYER M5 ;
        RECT  15.12 78.108 15.144 78.192 ;
    END
  END q[124]
  PIN q[125]
    DIRECTION OUTPUT ;
    USE SIGNAL ;
    PORT
      LAYER M5 ;
        RECT  15.408 78.108 15.432 78.192 ;
    END
  END q[125]
  PIN q[126]
    DIRECTION OUTPUT ;
    USE SIGNAL ;
    PORT
      LAYER M5 ;
        RECT  15.312 78.108 15.336 78.192 ;
    END
  END q[126]
  PIN q[127]
    DIRECTION OUTPUT ;
    USE SIGNAL ;
    PORT
      LAYER M5 ;
        RECT  15.696 78.108 15.72 78.192 ;
    END
  END q[127]
  PIN q[128]
    DIRECTION OUTPUT ;
    USE SIGNAL ;
    PORT
      LAYER M5 ;
        RECT  15.504 78.108 15.528 78.192 ;
    END
  END q[128]
  PIN q[129]
    DIRECTION OUTPUT ;
    USE SIGNAL ;
    PORT
      LAYER M5 ;
        RECT  15.792 78.108 15.816 78.192 ;
    END
  END q[129]
  PIN q[12]
    DIRECTION OUTPUT ;
    USE SIGNAL ;
    PORT
      LAYER M5 ;
        RECT  4.368 78.108 4.392 78.192 ;
    END
  END q[12]
  PIN q[130]
    DIRECTION OUTPUT ;
    USE SIGNAL ;
    PORT
      LAYER M5 ;
        RECT  15.6 78.108 15.624 78.192 ;
    END
  END q[130]
  PIN q[131]
    DIRECTION OUTPUT ;
    USE SIGNAL ;
    PORT
      LAYER M5 ;
        RECT  15.888 78.108 15.912 78.192 ;
    END
  END q[131]
  PIN q[132]
    DIRECTION OUTPUT ;
    USE SIGNAL ;
    PORT
      LAYER M5 ;
        RECT  16.08 78.108 16.104 78.192 ;
    END
  END q[132]
  PIN q[133]
    DIRECTION OUTPUT ;
    USE SIGNAL ;
    PORT
      LAYER M5 ;
        RECT  15.984 78.108 16.008 78.192 ;
    END
  END q[133]
  PIN q[134]
    DIRECTION OUTPUT ;
    USE SIGNAL ;
    PORT
      LAYER M5 ;
        RECT  16.272 78.108 16.296 78.192 ;
    END
  END q[134]
  PIN q[135]
    DIRECTION OUTPUT ;
    USE SIGNAL ;
    PORT
      LAYER M5 ;
        RECT  16.176 78.108 16.2 78.192 ;
    END
  END q[135]
  PIN q[136]
    DIRECTION OUTPUT ;
    USE SIGNAL ;
    PORT
      LAYER M5 ;
        RECT  16.464 78.108 16.488 78.192 ;
    END
  END q[136]
  PIN q[137]
    DIRECTION OUTPUT ;
    USE SIGNAL ;
    PORT
      LAYER M5 ;
        RECT  16.368 78.108 16.392 78.192 ;
    END
  END q[137]
  PIN q[138]
    DIRECTION OUTPUT ;
    USE SIGNAL ;
    PORT
      LAYER M5 ;
        RECT  16.656 78.108 16.68 78.192 ;
    END
  END q[138]
  PIN q[139]
    DIRECTION OUTPUT ;
    USE SIGNAL ;
    PORT
      LAYER M5 ;
        RECT  16.56 78.108 16.584 78.192 ;
    END
  END q[139]
  PIN q[13]
    DIRECTION OUTPUT ;
    USE SIGNAL ;
    PORT
      LAYER M5 ;
        RECT  4.656 78.108 4.68 78.192 ;
    END
  END q[13]
  PIN q[140]
    DIRECTION OUTPUT ;
    USE SIGNAL ;
    PORT
      LAYER M5 ;
        RECT  16.848 78.108 16.872 78.192 ;
    END
  END q[140]
  PIN q[141]
    DIRECTION OUTPUT ;
    USE SIGNAL ;
    PORT
      LAYER M5 ;
        RECT  16.752 78.108 16.776 78.192 ;
    END
  END q[141]
  PIN q[142]
    DIRECTION OUTPUT ;
    USE SIGNAL ;
    PORT
      LAYER M5 ;
        RECT  17.04 78.108 17.064 78.192 ;
    END
  END q[142]
  PIN q[143]
    DIRECTION OUTPUT ;
    USE SIGNAL ;
    PORT
      LAYER M5 ;
        RECT  16.944 78.108 16.968 78.192 ;
    END
  END q[143]
  PIN q[144]
    DIRECTION OUTPUT ;
    USE SIGNAL ;
    PORT
      LAYER M5 ;
        RECT  17.232 78.108 17.256 78.192 ;
    END
  END q[144]
  PIN q[145]
    DIRECTION OUTPUT ;
    USE SIGNAL ;
    PORT
      LAYER M5 ;
        RECT  17.136 78.108 17.16 78.192 ;
    END
  END q[145]
  PIN q[146]
    DIRECTION OUTPUT ;
    USE SIGNAL ;
    PORT
      LAYER M5 ;
        RECT  17.328 78.108 17.352 78.192 ;
    END
  END q[146]
  PIN q[147]
    DIRECTION OUTPUT ;
    USE SIGNAL ;
    PORT
      LAYER M5 ;
        RECT  17.424 78.108 17.448 78.192 ;
    END
  END q[147]
  PIN q[148]
    DIRECTION OUTPUT ;
    USE SIGNAL ;
    PORT
      LAYER M5 ;
        RECT  17.52 78.108 17.544 78.192 ;
    END
  END q[148]
  PIN q[149]
    DIRECTION OUTPUT ;
    USE SIGNAL ;
    PORT
      LAYER M5 ;
        RECT  17.616 78.108 17.64 78.192 ;
    END
  END q[149]
  PIN q[14]
    DIRECTION OUTPUT ;
    USE SIGNAL ;
    PORT
      LAYER M5 ;
        RECT  4.56 78.108 4.584 78.192 ;
    END
  END q[14]
  PIN q[150]
    DIRECTION OUTPUT ;
    USE SIGNAL ;
    PORT
      LAYER M5 ;
        RECT  17.712 78.108 17.736 78.192 ;
    END
  END q[150]
  PIN q[151]
    DIRECTION OUTPUT ;
    USE SIGNAL ;
    PORT
      LAYER M5 ;
        RECT  17.808 78.108 17.832 78.192 ;
    END
  END q[151]
  PIN q[152]
    DIRECTION OUTPUT ;
    USE SIGNAL ;
    PORT
      LAYER M5 ;
        RECT  17.904 78.108 17.928 78.192 ;
    END
  END q[152]
  PIN q[153]
    DIRECTION OUTPUT ;
    USE SIGNAL ;
    PORT
      LAYER M5 ;
        RECT  18 78.108 18.024 78.192 ;
    END
  END q[153]
  PIN q[154]
    DIRECTION OUTPUT ;
    USE SIGNAL ;
    PORT
      LAYER M5 ;
        RECT  18.096 78.108 18.12 78.192 ;
    END
  END q[154]
  PIN q[155]
    DIRECTION OUTPUT ;
    USE SIGNAL ;
    PORT
      LAYER M5 ;
        RECT  18.192 78.108 18.216 78.192 ;
    END
  END q[155]
  PIN q[156]
    DIRECTION OUTPUT ;
    USE SIGNAL ;
    PORT
      LAYER M5 ;
        RECT  18.288 78.108 18.312 78.192 ;
    END
  END q[156]
  PIN q[157]
    DIRECTION OUTPUT ;
    USE SIGNAL ;
    PORT
      LAYER M5 ;
        RECT  18.384 78.108 18.408 78.192 ;
    END
  END q[157]
  PIN q[158]
    DIRECTION OUTPUT ;
    USE SIGNAL ;
    PORT
      LAYER M5 ;
        RECT  18.48 78.108 18.504 78.192 ;
    END
  END q[158]
  PIN q[159]
    DIRECTION OUTPUT ;
    USE SIGNAL ;
    PORT
      LAYER M5 ;
        RECT  18.576 78.108 18.6 78.192 ;
    END
  END q[159]
  PIN q[15]
    DIRECTION OUTPUT ;
    USE SIGNAL ;
    PORT
      LAYER M5 ;
        RECT  4.848 78.108 4.872 78.192 ;
    END
  END q[15]
  PIN q[160]
    DIRECTION OUTPUT ;
    USE SIGNAL ;
    PORT
      LAYER M5 ;
        RECT  18.672 78.108 18.696 78.192 ;
    END
  END q[160]
  PIN q[161]
    DIRECTION OUTPUT ;
    USE SIGNAL ;
    PORT
      LAYER M5 ;
        RECT  18.768 78.108 18.792 78.192 ;
    END
  END q[161]
  PIN q[162]
    DIRECTION OUTPUT ;
    USE SIGNAL ;
    PORT
      LAYER M5 ;
        RECT  18.864 78.108 18.888 78.192 ;
    END
  END q[162]
  PIN q[163]
    DIRECTION OUTPUT ;
    USE SIGNAL ;
    PORT
      LAYER M5 ;
        RECT  19.056 78.108 19.08 78.192 ;
    END
  END q[163]
  PIN q[164]
    DIRECTION OUTPUT ;
    USE SIGNAL ;
    PORT
      LAYER M5 ;
        RECT  18.96 78.108 18.984 78.192 ;
    END
  END q[164]
  PIN q[165]
    DIRECTION OUTPUT ;
    USE SIGNAL ;
    PORT
      LAYER M5 ;
        RECT  19.248 78.108 19.272 78.192 ;
    END
  END q[165]
  PIN q[166]
    DIRECTION OUTPUT ;
    USE SIGNAL ;
    PORT
      LAYER M5 ;
        RECT  19.152 78.108 19.176 78.192 ;
    END
  END q[166]
  PIN q[167]
    DIRECTION OUTPUT ;
    USE SIGNAL ;
    PORT
      LAYER M5 ;
        RECT  19.44 78.108 19.464 78.192 ;
    END
  END q[167]
  PIN q[168]
    DIRECTION OUTPUT ;
    USE SIGNAL ;
    PORT
      LAYER M5 ;
        RECT  19.344 78.108 19.368 78.192 ;
    END
  END q[168]
  PIN q[169]
    DIRECTION OUTPUT ;
    USE SIGNAL ;
    PORT
      LAYER M5 ;
        RECT  19.728 78.108 19.752 78.192 ;
    END
  END q[169]
  PIN q[16]
    DIRECTION OUTPUT ;
    USE SIGNAL ;
    PORT
      LAYER M5 ;
        RECT  4.752 78.108 4.776 78.192 ;
    END
  END q[16]
  PIN q[170]
    DIRECTION OUTPUT ;
    USE SIGNAL ;
    PORT
      LAYER M5 ;
        RECT  19.536 78.108 19.56 78.192 ;
    END
  END q[170]
  PIN q[171]
    DIRECTION OUTPUT ;
    USE SIGNAL ;
    PORT
      LAYER M5 ;
        RECT  19.824 78.108 19.848 78.192 ;
    END
  END q[171]
  PIN q[172]
    DIRECTION OUTPUT ;
    USE SIGNAL ;
    PORT
      LAYER M5 ;
        RECT  19.632 78.108 19.656 78.192 ;
    END
  END q[172]
  PIN q[173]
    DIRECTION OUTPUT ;
    USE SIGNAL ;
    PORT
      LAYER M5 ;
        RECT  20.016 78.108 20.04 78.192 ;
    END
  END q[173]
  PIN q[174]
    DIRECTION OUTPUT ;
    USE SIGNAL ;
    PORT
      LAYER M5 ;
        RECT  19.92 78.108 19.944 78.192 ;
    END
  END q[174]
  PIN q[175]
    DIRECTION OUTPUT ;
    USE SIGNAL ;
    PORT
      LAYER M5 ;
        RECT  20.208 78.108 20.232 78.192 ;
    END
  END q[175]
  PIN q[176]
    DIRECTION OUTPUT ;
    USE SIGNAL ;
    PORT
      LAYER M5 ;
        RECT  20.112 78.108 20.136 78.192 ;
    END
  END q[176]
  PIN q[177]
    DIRECTION OUTPUT ;
    USE SIGNAL ;
    PORT
      LAYER M5 ;
        RECT  20.496 78.108 20.52 78.192 ;
    END
  END q[177]
  PIN q[178]
    DIRECTION OUTPUT ;
    USE SIGNAL ;
    PORT
      LAYER M5 ;
        RECT  20.304 78.108 20.328 78.192 ;
    END
  END q[178]
  PIN q[179]
    DIRECTION OUTPUT ;
    USE SIGNAL ;
    PORT
      LAYER M5 ;
        RECT  20.592 78.108 20.616 78.192 ;
    END
  END q[179]
  PIN q[17]
    DIRECTION OUTPUT ;
    USE SIGNAL ;
    PORT
      LAYER M5 ;
        RECT  5.04 78.108 5.064 78.192 ;
    END
  END q[17]
  PIN q[180]
    DIRECTION OUTPUT ;
    USE SIGNAL ;
    PORT
      LAYER M5 ;
        RECT  20.4 78.108 20.424 78.192 ;
    END
  END q[180]
  PIN q[181]
    DIRECTION OUTPUT ;
    USE SIGNAL ;
    PORT
      LAYER M5 ;
        RECT  20.688 78.108 20.712 78.192 ;
    END
  END q[181]
  PIN q[182]
    DIRECTION OUTPUT ;
    USE SIGNAL ;
    PORT
      LAYER M5 ;
        RECT  20.88 78.108 20.904 78.192 ;
    END
  END q[182]
  PIN q[183]
    DIRECTION OUTPUT ;
    USE SIGNAL ;
    PORT
      LAYER M5 ;
        RECT  20.784 78.108 20.808 78.192 ;
    END
  END q[183]
  PIN q[184]
    DIRECTION OUTPUT ;
    USE SIGNAL ;
    PORT
      LAYER M5 ;
        RECT  21.072 78.108 21.096 78.192 ;
    END
  END q[184]
  PIN q[185]
    DIRECTION OUTPUT ;
    USE SIGNAL ;
    PORT
      LAYER M5 ;
        RECT  20.976 78.108 21 78.192 ;
    END
  END q[185]
  PIN q[186]
    DIRECTION OUTPUT ;
    USE SIGNAL ;
    PORT
      LAYER M5 ;
        RECT  21.264 78.108 21.288 78.192 ;
    END
  END q[186]
  PIN q[187]
    DIRECTION OUTPUT ;
    USE SIGNAL ;
    PORT
      LAYER M5 ;
        RECT  21.168 78.108 21.192 78.192 ;
    END
  END q[187]
  PIN q[188]
    DIRECTION OUTPUT ;
    USE SIGNAL ;
    PORT
      LAYER M5 ;
        RECT  21.456 78.108 21.48 78.192 ;
    END
  END q[188]
  PIN q[189]
    DIRECTION OUTPUT ;
    USE SIGNAL ;
    PORT
      LAYER M5 ;
        RECT  21.36 78.108 21.384 78.192 ;
    END
  END q[189]
  PIN q[18]
    DIRECTION OUTPUT ;
    USE SIGNAL ;
    PORT
      LAYER M5 ;
        RECT  4.944 78.108 4.968 78.192 ;
    END
  END q[18]
  PIN q[190]
    DIRECTION OUTPUT ;
    USE SIGNAL ;
    PORT
      LAYER M5 ;
        RECT  21.648 78.108 21.672 78.192 ;
    END
  END q[190]
  PIN q[191]
    DIRECTION OUTPUT ;
    USE SIGNAL ;
    PORT
      LAYER M5 ;
        RECT  21.552 78.108 21.576 78.192 ;
    END
  END q[191]
  PIN q[192]
    DIRECTION OUTPUT ;
    USE SIGNAL ;
    PORT
      LAYER M5 ;
        RECT  21.84 78.108 21.864 78.192 ;
    END
  END q[192]
  PIN q[193]
    DIRECTION OUTPUT ;
    USE SIGNAL ;
    PORT
      LAYER M5 ;
        RECT  21.744 78.108 21.768 78.192 ;
    END
  END q[193]
  PIN q[194]
    DIRECTION OUTPUT ;
    USE SIGNAL ;
    PORT
      LAYER M5 ;
        RECT  21.936 78.108 21.96 78.192 ;
    END
  END q[194]
  PIN q[195]
    DIRECTION OUTPUT ;
    USE SIGNAL ;
    PORT
      LAYER M5 ;
        RECT  22.032 78.108 22.056 78.192 ;
    END
  END q[195]
  PIN q[196]
    DIRECTION OUTPUT ;
    USE SIGNAL ;
    PORT
      LAYER M5 ;
        RECT  22.128 78.108 22.152 78.192 ;
    END
  END q[196]
  PIN q[197]
    DIRECTION OUTPUT ;
    USE SIGNAL ;
    PORT
      LAYER M5 ;
        RECT  22.224 78.108 22.248 78.192 ;
    END
  END q[197]
  PIN q[198]
    DIRECTION OUTPUT ;
    USE SIGNAL ;
    PORT
      LAYER M5 ;
        RECT  22.32 78.108 22.344 78.192 ;
    END
  END q[198]
  PIN q[199]
    DIRECTION OUTPUT ;
    USE SIGNAL ;
    PORT
      LAYER M5 ;
        RECT  22.416 78.108 22.44 78.192 ;
    END
  END q[199]
  PIN q[19]
    DIRECTION OUTPUT ;
    USE SIGNAL ;
    PORT
      LAYER M5 ;
        RECT  5.232 78.108 5.256 78.192 ;
    END
  END q[19]
  PIN q[1]
    DIRECTION OUTPUT ;
    USE SIGNAL ;
    PORT
      LAYER M5 ;
        RECT  3.408 78.108 3.432 78.192 ;
    END
  END q[1]
  PIN q[200]
    DIRECTION OUTPUT ;
    USE SIGNAL ;
    PORT
      LAYER M5 ;
        RECT  22.512 78.108 22.536 78.192 ;
    END
  END q[200]
  PIN q[201]
    DIRECTION OUTPUT ;
    USE SIGNAL ;
    PORT
      LAYER M5 ;
        RECT  22.608 78.108 22.632 78.192 ;
    END
  END q[201]
  PIN q[202]
    DIRECTION OUTPUT ;
    USE SIGNAL ;
    PORT
      LAYER M5 ;
        RECT  22.704 78.108 22.728 78.192 ;
    END
  END q[202]
  PIN q[203]
    DIRECTION OUTPUT ;
    USE SIGNAL ;
    PORT
      LAYER M5 ;
        RECT  22.8 78.108 22.824 78.192 ;
    END
  END q[203]
  PIN q[204]
    DIRECTION OUTPUT ;
    USE SIGNAL ;
    PORT
      LAYER M5 ;
        RECT  22.896 78.108 22.92 78.192 ;
    END
  END q[204]
  PIN q[205]
    DIRECTION OUTPUT ;
    USE SIGNAL ;
    PORT
      LAYER M5 ;
        RECT  22.992 78.108 23.016 78.192 ;
    END
  END q[205]
  PIN q[206]
    DIRECTION OUTPUT ;
    USE SIGNAL ;
    PORT
      LAYER M5 ;
        RECT  23.088 78.108 23.112 78.192 ;
    END
  END q[206]
  PIN q[207]
    DIRECTION OUTPUT ;
    USE SIGNAL ;
    PORT
      LAYER M5 ;
        RECT  23.184 78.108 23.208 78.192 ;
    END
  END q[207]
  PIN q[208]
    DIRECTION OUTPUT ;
    USE SIGNAL ;
    PORT
      LAYER M5 ;
        RECT  23.28 78.108 23.304 78.192 ;
    END
  END q[208]
  PIN q[209]
    DIRECTION OUTPUT ;
    USE SIGNAL ;
    PORT
      LAYER M5 ;
        RECT  23.376 78.108 23.4 78.192 ;
    END
  END q[209]
  PIN q[20]
    DIRECTION OUTPUT ;
    USE SIGNAL ;
    PORT
      LAYER M5 ;
        RECT  5.136 78.108 5.16 78.192 ;
    END
  END q[20]
  PIN q[210]
    DIRECTION OUTPUT ;
    USE SIGNAL ;
    PORT
      LAYER M5 ;
        RECT  23.472 78.108 23.496 78.192 ;
    END
  END q[210]
  PIN q[211]
    DIRECTION OUTPUT ;
    USE SIGNAL ;
    PORT
      LAYER M5 ;
        RECT  23.568 78.108 23.592 78.192 ;
    END
  END q[211]
  PIN q[212]
    DIRECTION OUTPUT ;
    USE SIGNAL ;
    PORT
      LAYER M5 ;
        RECT  23.664 78.108 23.688 78.192 ;
    END
  END q[212]
  PIN q[213]
    DIRECTION OUTPUT ;
    USE SIGNAL ;
    PORT
      LAYER M5 ;
        RECT  23.856 78.108 23.88 78.192 ;
    END
  END q[213]
  PIN q[214]
    DIRECTION OUTPUT ;
    USE SIGNAL ;
    PORT
      LAYER M5 ;
        RECT  23.76 78.108 23.784 78.192 ;
    END
  END q[214]
  PIN q[215]
    DIRECTION OUTPUT ;
    USE SIGNAL ;
    PORT
      LAYER M5 ;
        RECT  24.048 78.108 24.072 78.192 ;
    END
  END q[215]
  PIN q[216]
    DIRECTION OUTPUT ;
    USE SIGNAL ;
    PORT
      LAYER M5 ;
        RECT  23.952 78.108 23.976 78.192 ;
    END
  END q[216]
  PIN q[217]
    DIRECTION OUTPUT ;
    USE SIGNAL ;
    PORT
      LAYER M5 ;
        RECT  24.24 78.108 24.264 78.192 ;
    END
  END q[217]
  PIN q[218]
    DIRECTION OUTPUT ;
    USE SIGNAL ;
    PORT
      LAYER M5 ;
        RECT  24.144 78.108 24.168 78.192 ;
    END
  END q[218]
  PIN q[219]
    DIRECTION OUTPUT ;
    USE SIGNAL ;
    PORT
      LAYER M5 ;
        RECT  24.528 78.108 24.552 78.192 ;
    END
  END q[219]
  PIN q[21]
    DIRECTION OUTPUT ;
    USE SIGNAL ;
    PORT
      LAYER M5 ;
        RECT  5.424 78.108 5.448 78.192 ;
    END
  END q[21]
  PIN q[220]
    DIRECTION OUTPUT ;
    USE SIGNAL ;
    PORT
      LAYER M5 ;
        RECT  24.336 78.108 24.36 78.192 ;
    END
  END q[220]
  PIN q[221]
    DIRECTION OUTPUT ;
    USE SIGNAL ;
    PORT
      LAYER M5 ;
        RECT  24.624 78.108 24.648 78.192 ;
    END
  END q[221]
  PIN q[222]
    DIRECTION OUTPUT ;
    USE SIGNAL ;
    PORT
      LAYER M5 ;
        RECT  24.432 78.108 24.456 78.192 ;
    END
  END q[222]
  PIN q[223]
    DIRECTION OUTPUT ;
    USE SIGNAL ;
    PORT
      LAYER M5 ;
        RECT  24.816 78.108 24.84 78.192 ;
    END
  END q[223]
  PIN q[224]
    DIRECTION OUTPUT ;
    USE SIGNAL ;
    PORT
      LAYER M5 ;
        RECT  24.72 78.108 24.744 78.192 ;
    END
  END q[224]
  PIN q[225]
    DIRECTION OUTPUT ;
    USE SIGNAL ;
    PORT
      LAYER M5 ;
        RECT  25.008 78.108 25.032 78.192 ;
    END
  END q[225]
  PIN q[226]
    DIRECTION OUTPUT ;
    USE SIGNAL ;
    PORT
      LAYER M5 ;
        RECT  24.912 78.108 24.936 78.192 ;
    END
  END q[226]
  PIN q[227]
    DIRECTION OUTPUT ;
    USE SIGNAL ;
    PORT
      LAYER M5 ;
        RECT  26.16 78.108 26.184 78.192 ;
    END
  END q[227]
  PIN q[228]
    DIRECTION OUTPUT ;
    USE SIGNAL ;
    PORT
      LAYER M5 ;
        RECT  25.104 78.108 25.128 78.192 ;
    END
  END q[228]
  PIN q[229]
    DIRECTION OUTPUT ;
    USE SIGNAL ;
    PORT
      LAYER M5 ;
        RECT  26.352 78.108 26.376 78.192 ;
    END
  END q[229]
  PIN q[22]
    DIRECTION OUTPUT ;
    USE SIGNAL ;
    PORT
      LAYER M5 ;
        RECT  5.328 78.108 5.352 78.192 ;
    END
  END q[22]
  PIN q[230]
    DIRECTION OUTPUT ;
    USE SIGNAL ;
    PORT
      LAYER M5 ;
        RECT  26.256 78.108 26.28 78.192 ;
    END
  END q[230]
  PIN q[231]
    DIRECTION OUTPUT ;
    USE SIGNAL ;
    PORT
      LAYER M5 ;
        RECT  26.448 78.108 26.472 78.192 ;
    END
  END q[231]
  PIN q[232]
    DIRECTION OUTPUT ;
    USE SIGNAL ;
    PORT
      LAYER M5 ;
        RECT  26.64 78.108 26.664 78.192 ;
    END
  END q[232]
  PIN q[233]
    DIRECTION OUTPUT ;
    USE SIGNAL ;
    PORT
      LAYER M5 ;
        RECT  26.544 78.108 26.568 78.192 ;
    END
  END q[233]
  PIN q[234]
    DIRECTION OUTPUT ;
    USE SIGNAL ;
    PORT
      LAYER M5 ;
        RECT  26.832 78.108 26.856 78.192 ;
    END
  END q[234]
  PIN q[235]
    DIRECTION OUTPUT ;
    USE SIGNAL ;
    PORT
      LAYER M5 ;
        RECT  26.736 78.108 26.76 78.192 ;
    END
  END q[235]
  PIN q[236]
    DIRECTION OUTPUT ;
    USE SIGNAL ;
    PORT
      LAYER M5 ;
        RECT  27.024 78.108 27.048 78.192 ;
    END
  END q[236]
  PIN q[237]
    DIRECTION OUTPUT ;
    USE SIGNAL ;
    PORT
      LAYER M5 ;
        RECT  26.928 78.108 26.952 78.192 ;
    END
  END q[237]
  PIN q[238]
    DIRECTION OUTPUT ;
    USE SIGNAL ;
    PORT
      LAYER M5 ;
        RECT  27.216 78.108 27.24 78.192 ;
    END
  END q[238]
  PIN q[239]
    DIRECTION OUTPUT ;
    USE SIGNAL ;
    PORT
      LAYER M5 ;
        RECT  27.12 78.108 27.144 78.192 ;
    END
  END q[239]
  PIN q[23]
    DIRECTION OUTPUT ;
    USE SIGNAL ;
    PORT
      LAYER M5 ;
        RECT  5.616 78.108 5.64 78.192 ;
    END
  END q[23]
  PIN q[240]
    DIRECTION OUTPUT ;
    USE SIGNAL ;
    PORT
      LAYER M5 ;
        RECT  27.408 78.108 27.432 78.192 ;
    END
  END q[240]
  PIN q[241]
    DIRECTION OUTPUT ;
    USE SIGNAL ;
    PORT
      LAYER M5 ;
        RECT  27.312 78.108 27.336 78.192 ;
    END
  END q[241]
  PIN q[242]
    DIRECTION OUTPUT ;
    USE SIGNAL ;
    PORT
      LAYER M5 ;
        RECT  27.6 78.108 27.624 78.192 ;
    END
  END q[242]
  PIN q[243]
    DIRECTION OUTPUT ;
    USE SIGNAL ;
    PORT
      LAYER M5 ;
        RECT  27.504 78.108 27.528 78.192 ;
    END
  END q[243]
  PIN q[244]
    DIRECTION OUTPUT ;
    USE SIGNAL ;
    PORT
      LAYER M5 ;
        RECT  27.696 78.108 27.72 78.192 ;
    END
  END q[244]
  PIN q[245]
    DIRECTION OUTPUT ;
    USE SIGNAL ;
    PORT
      LAYER M5 ;
        RECT  27.792 78.108 27.816 78.192 ;
    END
  END q[245]
  PIN q[246]
    DIRECTION OUTPUT ;
    USE SIGNAL ;
    PORT
      LAYER M5 ;
        RECT  27.984 78.108 28.008 78.192 ;
    END
  END q[246]
  PIN q[247]
    DIRECTION OUTPUT ;
    USE SIGNAL ;
    PORT
      LAYER M5 ;
        RECT  27.888 78.108 27.912 78.192 ;
    END
  END q[247]
  PIN q[248]
    DIRECTION OUTPUT ;
    USE SIGNAL ;
    PORT
      LAYER M5 ;
        RECT  28.176 78.108 28.2 78.192 ;
    END
  END q[248]
  PIN q[249]
    DIRECTION OUTPUT ;
    USE SIGNAL ;
    PORT
      LAYER M5 ;
        RECT  28.08 78.108 28.104 78.192 ;
    END
  END q[249]
  PIN q[24]
    DIRECTION OUTPUT ;
    USE SIGNAL ;
    PORT
      LAYER M5 ;
        RECT  5.52 78.108 5.544 78.192 ;
    END
  END q[24]
  PIN q[250]
    DIRECTION OUTPUT ;
    USE SIGNAL ;
    PORT
      LAYER M5 ;
        RECT  28.272 78.108 28.296 78.192 ;
    END
  END q[250]
  PIN q[251]
    DIRECTION OUTPUT ;
    USE SIGNAL ;
    PORT
      LAYER M5 ;
        RECT  28.368 78.108 28.392 78.192 ;
    END
  END q[251]
  PIN q[252]
    DIRECTION OUTPUT ;
    USE SIGNAL ;
    PORT
      LAYER M5 ;
        RECT  28.464 78.108 28.488 78.192 ;
    END
  END q[252]
  PIN q[253]
    DIRECTION OUTPUT ;
    USE SIGNAL ;
    PORT
      LAYER M5 ;
        RECT  28.56 78.108 28.584 78.192 ;
    END
  END q[253]
  PIN q[254]
    DIRECTION OUTPUT ;
    USE SIGNAL ;
    PORT
      LAYER M5 ;
        RECT  28.656 78.108 28.68 78.192 ;
    END
  END q[254]
  PIN q[255]
    DIRECTION OUTPUT ;
    USE SIGNAL ;
    PORT
      LAYER M5 ;
        RECT  28.752 78.108 28.776 78.192 ;
    END
  END q[255]
  PIN q[256]
    DIRECTION OUTPUT ;
    USE SIGNAL ;
    PORT
      LAYER M5 ;
        RECT  28.848 78.108 28.872 78.192 ;
    END
  END q[256]
  PIN q[257]
    DIRECTION OUTPUT ;
    USE SIGNAL ;
    PORT
      LAYER M5 ;
        RECT  28.944 78.108 28.968 78.192 ;
    END
  END q[257]
  PIN q[258]
    DIRECTION OUTPUT ;
    USE SIGNAL ;
    PORT
      LAYER M5 ;
        RECT  29.04 78.108 29.064 78.192 ;
    END
  END q[258]
  PIN q[259]
    DIRECTION OUTPUT ;
    USE SIGNAL ;
    PORT
      LAYER M5 ;
        RECT  29.136 78.108 29.16 78.192 ;
    END
  END q[259]
  PIN q[25]
    DIRECTION OUTPUT ;
    USE SIGNAL ;
    PORT
      LAYER M5 ;
        RECT  5.904 78.108 5.928 78.192 ;
    END
  END q[25]
  PIN q[260]
    DIRECTION OUTPUT ;
    USE SIGNAL ;
    PORT
      LAYER M5 ;
        RECT  29.232 78.108 29.256 78.192 ;
    END
  END q[260]
  PIN q[261]
    DIRECTION OUTPUT ;
    USE SIGNAL ;
    PORT
      LAYER M5 ;
        RECT  29.328 78.108 29.352 78.192 ;
    END
  END q[261]
  PIN q[262]
    DIRECTION OUTPUT ;
    USE SIGNAL ;
    PORT
      LAYER M5 ;
        RECT  29.424 78.108 29.448 78.192 ;
    END
  END q[262]
  PIN q[263]
    DIRECTION OUTPUT ;
    USE SIGNAL ;
    PORT
      LAYER M5 ;
        RECT  29.52 78.108 29.544 78.192 ;
    END
  END q[263]
  PIN q[264]
    DIRECTION OUTPUT ;
    USE SIGNAL ;
    PORT
      LAYER M5 ;
        RECT  29.616 78.108 29.64 78.192 ;
    END
  END q[264]
  PIN q[265]
    DIRECTION OUTPUT ;
    USE SIGNAL ;
    PORT
      LAYER M5 ;
        RECT  29.712 78.108 29.736 78.192 ;
    END
  END q[265]
  PIN q[266]
    DIRECTION OUTPUT ;
    USE SIGNAL ;
    PORT
      LAYER M5 ;
        RECT  29.808 78.108 29.832 78.192 ;
    END
  END q[266]
  PIN q[267]
    DIRECTION OUTPUT ;
    USE SIGNAL ;
    PORT
      LAYER M5 ;
        RECT  30 78.108 30.024 78.192 ;
    END
  END q[267]
  PIN q[268]
    DIRECTION OUTPUT ;
    USE SIGNAL ;
    PORT
      LAYER M5 ;
        RECT  29.904 78.108 29.928 78.192 ;
    END
  END q[268]
  PIN q[269]
    DIRECTION OUTPUT ;
    USE SIGNAL ;
    PORT
      LAYER M5 ;
        RECT  30.096 78.108 30.12 78.192 ;
    END
  END q[269]
  PIN q[26]
    DIRECTION OUTPUT ;
    USE SIGNAL ;
    PORT
      LAYER M5 ;
        RECT  5.712 78.108 5.736 78.192 ;
    END
  END q[26]
  PIN q[270]
    DIRECTION OUTPUT ;
    USE SIGNAL ;
    PORT
      LAYER M5 ;
        RECT  30.192 78.108 30.216 78.192 ;
    END
  END q[270]
  PIN q[271]
    DIRECTION OUTPUT ;
    USE SIGNAL ;
    PORT
      LAYER M5 ;
        RECT  30.384 78.108 30.408 78.192 ;
    END
  END q[271]
  PIN q[272]
    DIRECTION OUTPUT ;
    USE SIGNAL ;
    PORT
      LAYER M5 ;
        RECT  30.288 78.108 30.312 78.192 ;
    END
  END q[272]
  PIN q[273]
    DIRECTION OUTPUT ;
    USE SIGNAL ;
    PORT
      LAYER M5 ;
        RECT  30.576 78.108 30.6 78.192 ;
    END
  END q[273]
  PIN q[274]
    DIRECTION OUTPUT ;
    USE SIGNAL ;
    PORT
      LAYER M5 ;
        RECT  30.48 78.108 30.504 78.192 ;
    END
  END q[274]
  PIN q[275]
    DIRECTION OUTPUT ;
    USE SIGNAL ;
    PORT
      LAYER M5 ;
        RECT  30.768 78.108 30.792 78.192 ;
    END
  END q[275]
  PIN q[276]
    DIRECTION OUTPUT ;
    USE SIGNAL ;
    PORT
      LAYER M5 ;
        RECT  30.672 78.108 30.696 78.192 ;
    END
  END q[276]
  PIN q[277]
    DIRECTION OUTPUT ;
    USE SIGNAL ;
    PORT
      LAYER M5 ;
        RECT  30.96 78.108 30.984 78.192 ;
    END
  END q[277]
  PIN q[278]
    DIRECTION OUTPUT ;
    USE SIGNAL ;
    PORT
      LAYER M5 ;
        RECT  30.864 78.108 30.888 78.192 ;
    END
  END q[278]
  PIN q[279]
    DIRECTION OUTPUT ;
    USE SIGNAL ;
    PORT
      LAYER M5 ;
        RECT  31.152 78.108 31.176 78.192 ;
    END
  END q[279]
  PIN q[27]
    DIRECTION OUTPUT ;
    USE SIGNAL ;
    PORT
      LAYER M5 ;
        RECT  6.096 78.108 6.12 78.192 ;
    END
  END q[27]
  PIN q[280]
    DIRECTION OUTPUT ;
    USE SIGNAL ;
    PORT
      LAYER M5 ;
        RECT  31.056 78.108 31.08 78.192 ;
    END
  END q[280]
  PIN q[281]
    DIRECTION OUTPUT ;
    USE SIGNAL ;
    PORT
      LAYER M5 ;
        RECT  31.248 78.108 31.272 78.192 ;
    END
  END q[281]
  PIN q[282]
    DIRECTION OUTPUT ;
    USE SIGNAL ;
    PORT
      LAYER M5 ;
        RECT  31.44 78.108 31.464 78.192 ;
    END
  END q[282]
  PIN q[283]
    DIRECTION OUTPUT ;
    USE SIGNAL ;
    PORT
      LAYER M5 ;
        RECT  31.344 78.108 31.368 78.192 ;
    END
  END q[283]
  PIN q[284]
    DIRECTION OUTPUT ;
    USE SIGNAL ;
    PORT
      LAYER M5 ;
        RECT  31.632 78.108 31.656 78.192 ;
    END
  END q[284]
  PIN q[285]
    DIRECTION OUTPUT ;
    USE SIGNAL ;
    PORT
      LAYER M5 ;
        RECT  31.536 78.108 31.56 78.192 ;
    END
  END q[285]
  PIN q[286]
    DIRECTION OUTPUT ;
    USE SIGNAL ;
    PORT
      LAYER M5 ;
        RECT  31.824 78.108 31.848 78.192 ;
    END
  END q[286]
  PIN q[287]
    DIRECTION OUTPUT ;
    USE SIGNAL ;
    PORT
      LAYER M5 ;
        RECT  31.728 78.108 31.752 78.192 ;
    END
  END q[287]
  PIN q[288]
    DIRECTION OUTPUT ;
    USE SIGNAL ;
    PORT
      LAYER M5 ;
        RECT  32.016 78.108 32.04 78.192 ;
    END
  END q[288]
  PIN q[289]
    DIRECTION OUTPUT ;
    USE SIGNAL ;
    PORT
      LAYER M5 ;
        RECT  31.92 78.108 31.944 78.192 ;
    END
  END q[289]
  PIN q[28]
    DIRECTION OUTPUT ;
    USE SIGNAL ;
    PORT
      LAYER M5 ;
        RECT  5.808 78.108 5.832 78.192 ;
    END
  END q[28]
  PIN q[290]
    DIRECTION OUTPUT ;
    USE SIGNAL ;
    PORT
      LAYER M5 ;
        RECT  32.208 78.108 32.232 78.192 ;
    END
  END q[290]
  PIN q[291]
    DIRECTION OUTPUT ;
    USE SIGNAL ;
    PORT
      LAYER M5 ;
        RECT  32.112 78.108 32.136 78.192 ;
    END
  END q[291]
  PIN q[292]
    DIRECTION OUTPUT ;
    USE SIGNAL ;
    PORT
      LAYER M5 ;
        RECT  32.4 78.108 32.424 78.192 ;
    END
  END q[292]
  PIN q[293]
    DIRECTION OUTPUT ;
    USE SIGNAL ;
    PORT
      LAYER M5 ;
        RECT  32.304 78.108 32.328 78.192 ;
    END
  END q[293]
  PIN q[294]
    DIRECTION OUTPUT ;
    USE SIGNAL ;
    PORT
      LAYER M5 ;
        RECT  32.496 78.108 32.52 78.192 ;
    END
  END q[294]
  PIN q[295]
    DIRECTION OUTPUT ;
    USE SIGNAL ;
    PORT
      LAYER M5 ;
        RECT  32.592 78.108 32.616 78.192 ;
    END
  END q[295]
  PIN q[296]
    DIRECTION OUTPUT ;
    USE SIGNAL ;
    PORT
      LAYER M5 ;
        RECT  32.784 78.108 32.808 78.192 ;
    END
  END q[296]
  PIN q[297]
    DIRECTION OUTPUT ;
    USE SIGNAL ;
    PORT
      LAYER M5 ;
        RECT  32.688 78.108 32.712 78.192 ;
    END
  END q[297]
  PIN q[298]
    DIRECTION OUTPUT ;
    USE SIGNAL ;
    PORT
      LAYER M5 ;
        RECT  32.88 78.108 32.904 78.192 ;
    END
  END q[298]
  PIN q[299]
    DIRECTION OUTPUT ;
    USE SIGNAL ;
    PORT
      LAYER M5 ;
        RECT  32.976 78.108 33 78.192 ;
    END
  END q[299]
  PIN q[29]
    DIRECTION OUTPUT ;
    USE SIGNAL ;
    PORT
      LAYER M5 ;
        RECT  6.192 78.108 6.216 78.192 ;
    END
  END q[29]
  PIN q[2]
    DIRECTION OUTPUT ;
    USE SIGNAL ;
    PORT
      LAYER M5 ;
        RECT  3.504 78.108 3.528 78.192 ;
    END
  END q[2]
  PIN q[300]
    DIRECTION OUTPUT ;
    USE SIGNAL ;
    PORT
      LAYER M5 ;
        RECT  33.072 78.108 33.096 78.192 ;
    END
  END q[300]
  PIN q[301]
    DIRECTION OUTPUT ;
    USE SIGNAL ;
    PORT
      LAYER M5 ;
        RECT  33.168 78.108 33.192 78.192 ;
    END
  END q[301]
  PIN q[302]
    DIRECTION OUTPUT ;
    USE SIGNAL ;
    PORT
      LAYER M5 ;
        RECT  33.264 78.108 33.288 78.192 ;
    END
  END q[302]
  PIN q[303]
    DIRECTION OUTPUT ;
    USE SIGNAL ;
    PORT
      LAYER M5 ;
        RECT  33.36 78.108 33.384 78.192 ;
    END
  END q[303]
  PIN q[304]
    DIRECTION OUTPUT ;
    USE SIGNAL ;
    PORT
      LAYER M5 ;
        RECT  33.456 78.108 33.48 78.192 ;
    END
  END q[304]
  PIN q[305]
    DIRECTION OUTPUT ;
    USE SIGNAL ;
    PORT
      LAYER M5 ;
        RECT  33.552 78.108 33.576 78.192 ;
    END
  END q[305]
  PIN q[306]
    DIRECTION OUTPUT ;
    USE SIGNAL ;
    PORT
      LAYER M5 ;
        RECT  33.648 78.108 33.672 78.192 ;
    END
  END q[306]
  PIN q[307]
    DIRECTION OUTPUT ;
    USE SIGNAL ;
    PORT
      LAYER M5 ;
        RECT  33.744 78.108 33.768 78.192 ;
    END
  END q[307]
  PIN q[308]
    DIRECTION OUTPUT ;
    USE SIGNAL ;
    PORT
      LAYER M5 ;
        RECT  33.84 78.108 33.864 78.192 ;
    END
  END q[308]
  PIN q[309]
    DIRECTION OUTPUT ;
    USE SIGNAL ;
    PORT
      LAYER M5 ;
        RECT  33.936 78.108 33.96 78.192 ;
    END
  END q[309]
  PIN q[30]
    DIRECTION OUTPUT ;
    USE SIGNAL ;
    PORT
      LAYER M5 ;
        RECT  6 78.108 6.024 78.192 ;
    END
  END q[30]
  PIN q[310]
    DIRECTION OUTPUT ;
    USE SIGNAL ;
    PORT
      LAYER M5 ;
        RECT  34.032 78.108 34.056 78.192 ;
    END
  END q[310]
  PIN q[311]
    DIRECTION OUTPUT ;
    USE SIGNAL ;
    PORT
      LAYER M5 ;
        RECT  34.128 78.108 34.152 78.192 ;
    END
  END q[311]
  PIN q[312]
    DIRECTION OUTPUT ;
    USE SIGNAL ;
    PORT
      LAYER M5 ;
        RECT  34.224 78.108 34.248 78.192 ;
    END
  END q[312]
  PIN q[313]
    DIRECTION OUTPUT ;
    USE SIGNAL ;
    PORT
      LAYER M5 ;
        RECT  34.32 78.108 34.344 78.192 ;
    END
  END q[313]
  PIN q[314]
    DIRECTION OUTPUT ;
    USE SIGNAL ;
    PORT
      LAYER M5 ;
        RECT  34.416 78.108 34.44 78.192 ;
    END
  END q[314]
  PIN q[315]
    DIRECTION OUTPUT ;
    USE SIGNAL ;
    PORT
      LAYER M5 ;
        RECT  34.512 78.108 34.536 78.192 ;
    END
  END q[315]
  PIN q[316]
    DIRECTION OUTPUT ;
    USE SIGNAL ;
    PORT
      LAYER M5 ;
        RECT  34.608 78.108 34.632 78.192 ;
    END
  END q[316]
  PIN q[317]
    DIRECTION OUTPUT ;
    USE SIGNAL ;
    PORT
      LAYER M5 ;
        RECT  34.8 78.108 34.824 78.192 ;
    END
  END q[317]
  PIN q[318]
    DIRECTION OUTPUT ;
    USE SIGNAL ;
    PORT
      LAYER M5 ;
        RECT  34.704 78.108 34.728 78.192 ;
    END
  END q[318]
  PIN q[319]
    DIRECTION OUTPUT ;
    USE SIGNAL ;
    PORT
      LAYER M5 ;
        RECT  34.896 78.108 34.92 78.192 ;
    END
  END q[319]
  PIN q[31]
    DIRECTION OUTPUT ;
    USE SIGNAL ;
    PORT
      LAYER M5 ;
        RECT  6.288 78.108 6.312 78.192 ;
    END
  END q[31]
  PIN q[320]
    DIRECTION OUTPUT ;
    USE SIGNAL ;
    PORT
      LAYER M5 ;
        RECT  34.992 78.108 35.016 78.192 ;
    END
  END q[320]
  PIN q[321]
    DIRECTION OUTPUT ;
    USE SIGNAL ;
    PORT
      LAYER M5 ;
        RECT  35.184 78.108 35.208 78.192 ;
    END
  END q[321]
  PIN q[322]
    DIRECTION OUTPUT ;
    USE SIGNAL ;
    PORT
      LAYER M5 ;
        RECT  35.088 78.108 35.112 78.192 ;
    END
  END q[322]
  PIN q[323]
    DIRECTION OUTPUT ;
    USE SIGNAL ;
    PORT
      LAYER M5 ;
        RECT  35.376 78.108 35.4 78.192 ;
    END
  END q[323]
  PIN q[324]
    DIRECTION OUTPUT ;
    USE SIGNAL ;
    PORT
      LAYER M5 ;
        RECT  35.28 78.108 35.304 78.192 ;
    END
  END q[324]
  PIN q[325]
    DIRECTION OUTPUT ;
    USE SIGNAL ;
    PORT
      LAYER M5 ;
        RECT  35.568 78.108 35.592 78.192 ;
    END
  END q[325]
  PIN q[326]
    DIRECTION OUTPUT ;
    USE SIGNAL ;
    PORT
      LAYER M5 ;
        RECT  35.472 78.108 35.496 78.192 ;
    END
  END q[326]
  PIN q[327]
    DIRECTION OUTPUT ;
    USE SIGNAL ;
    PORT
      LAYER M5 ;
        RECT  35.76 78.108 35.784 78.192 ;
    END
  END q[327]
  PIN q[328]
    DIRECTION OUTPUT ;
    USE SIGNAL ;
    PORT
      LAYER M5 ;
        RECT  35.664 78.108 35.688 78.192 ;
    END
  END q[328]
  PIN q[329]
    DIRECTION OUTPUT ;
    USE SIGNAL ;
    PORT
      LAYER M5 ;
        RECT  35.952 78.108 35.976 78.192 ;
    END
  END q[329]
  PIN q[32]
    DIRECTION OUTPUT ;
    USE SIGNAL ;
    PORT
      LAYER M5 ;
        RECT  6.48 78.108 6.504 78.192 ;
    END
  END q[32]
  PIN q[330]
    DIRECTION OUTPUT ;
    USE SIGNAL ;
    PORT
      LAYER M5 ;
        RECT  35.856 78.108 35.88 78.192 ;
    END
  END q[330]
  PIN q[331]
    DIRECTION OUTPUT ;
    USE SIGNAL ;
    PORT
      LAYER M5 ;
        RECT  36.144 78.108 36.168 78.192 ;
    END
  END q[331]
  PIN q[332]
    DIRECTION OUTPUT ;
    USE SIGNAL ;
    PORT
      LAYER M5 ;
        RECT  36.048 78.108 36.072 78.192 ;
    END
  END q[332]
  PIN q[333]
    DIRECTION OUTPUT ;
    USE SIGNAL ;
    PORT
      LAYER M5 ;
        RECT  36.24 78.108 36.264 78.192 ;
    END
  END q[333]
  PIN q[334]
    DIRECTION OUTPUT ;
    USE SIGNAL ;
    PORT
      LAYER M5 ;
        RECT  36.432 78.108 36.456 78.192 ;
    END
  END q[334]
  PIN q[335]
    DIRECTION OUTPUT ;
    USE SIGNAL ;
    PORT
      LAYER M5 ;
        RECT  36.336 78.108 36.36 78.192 ;
    END
  END q[335]
  PIN q[336]
    DIRECTION OUTPUT ;
    USE SIGNAL ;
    PORT
      LAYER M5 ;
        RECT  36.624 78.108 36.648 78.192 ;
    END
  END q[336]
  PIN q[337]
    DIRECTION OUTPUT ;
    USE SIGNAL ;
    PORT
      LAYER M5 ;
        RECT  36.528 78.108 36.552 78.192 ;
    END
  END q[337]
  PIN q[338]
    DIRECTION OUTPUT ;
    USE SIGNAL ;
    PORT
      LAYER M5 ;
        RECT  36.816 78.108 36.84 78.192 ;
    END
  END q[338]
  PIN q[339]
    DIRECTION OUTPUT ;
    USE SIGNAL ;
    PORT
      LAYER M5 ;
        RECT  36.72 78.108 36.744 78.192 ;
    END
  END q[339]
  PIN q[33]
    DIRECTION OUTPUT ;
    USE SIGNAL ;
    PORT
      LAYER M5 ;
        RECT  6.384 78.108 6.408 78.192 ;
    END
  END q[33]
  PIN q[340]
    DIRECTION OUTPUT ;
    USE SIGNAL ;
    PORT
      LAYER M5 ;
        RECT  37.008 78.108 37.032 78.192 ;
    END
  END q[340]
  PIN q[341]
    DIRECTION OUTPUT ;
    USE SIGNAL ;
    PORT
      LAYER M5 ;
        RECT  36.912 78.108 36.936 78.192 ;
    END
  END q[341]
  PIN q[342]
    DIRECTION OUTPUT ;
    USE SIGNAL ;
    PORT
      LAYER M5 ;
        RECT  37.2 78.108 37.224 78.192 ;
    END
  END q[342]
  PIN q[343]
    DIRECTION OUTPUT ;
    USE SIGNAL ;
    PORT
      LAYER M5 ;
        RECT  37.104 78.108 37.128 78.192 ;
    END
  END q[343]
  PIN q[344]
    DIRECTION OUTPUT ;
    USE SIGNAL ;
    PORT
      LAYER M5 ;
        RECT  37.296 78.108 37.32 78.192 ;
    END
  END q[344]
  PIN q[345]
    DIRECTION OUTPUT ;
    USE SIGNAL ;
    PORT
      LAYER M5 ;
        RECT  37.392 78.108 37.416 78.192 ;
    END
  END q[345]
  PIN q[346]
    DIRECTION OUTPUT ;
    USE SIGNAL ;
    PORT
      LAYER M5 ;
        RECT  37.584 78.108 37.608 78.192 ;
    END
  END q[346]
  PIN q[347]
    DIRECTION OUTPUT ;
    USE SIGNAL ;
    PORT
      LAYER M5 ;
        RECT  37.488 78.108 37.512 78.192 ;
    END
  END q[347]
  PIN q[348]
    DIRECTION OUTPUT ;
    USE SIGNAL ;
    PORT
      LAYER M5 ;
        RECT  37.68 78.108 37.704 78.192 ;
    END
  END q[348]
  PIN q[349]
    DIRECTION OUTPUT ;
    USE SIGNAL ;
    PORT
      LAYER M5 ;
        RECT  37.776 78.108 37.8 78.192 ;
    END
  END q[349]
  PIN q[34]
    DIRECTION OUTPUT ;
    USE SIGNAL ;
    PORT
      LAYER M5 ;
        RECT  6.672 78.108 6.696 78.192 ;
    END
  END q[34]
  PIN q[350]
    DIRECTION OUTPUT ;
    USE SIGNAL ;
    PORT
      LAYER M5 ;
        RECT  37.872 78.108 37.896 78.192 ;
    END
  END q[350]
  PIN q[351]
    DIRECTION OUTPUT ;
    USE SIGNAL ;
    PORT
      LAYER M5 ;
        RECT  37.968 78.108 37.992 78.192 ;
    END
  END q[351]
  PIN q[352]
    DIRECTION OUTPUT ;
    USE SIGNAL ;
    PORT
      LAYER M5 ;
        RECT  38.064 78.108 38.088 78.192 ;
    END
  END q[352]
  PIN q[353]
    DIRECTION OUTPUT ;
    USE SIGNAL ;
    PORT
      LAYER M5 ;
        RECT  38.16 78.108 38.184 78.192 ;
    END
  END q[353]
  PIN q[354]
    DIRECTION OUTPUT ;
    USE SIGNAL ;
    PORT
      LAYER M5 ;
        RECT  38.256 78.108 38.28 78.192 ;
    END
  END q[354]
  PIN q[355]
    DIRECTION OUTPUT ;
    USE SIGNAL ;
    PORT
      LAYER M5 ;
        RECT  38.352 78.108 38.376 78.192 ;
    END
  END q[355]
  PIN q[356]
    DIRECTION OUTPUT ;
    USE SIGNAL ;
    PORT
      LAYER M5 ;
        RECT  38.448 78.108 38.472 78.192 ;
    END
  END q[356]
  PIN q[357]
    DIRECTION OUTPUT ;
    USE SIGNAL ;
    PORT
      LAYER M5 ;
        RECT  38.544 78.108 38.568 78.192 ;
    END
  END q[357]
  PIN q[358]
    DIRECTION OUTPUT ;
    USE SIGNAL ;
    PORT
      LAYER M5 ;
        RECT  38.64 78.108 38.664 78.192 ;
    END
  END q[358]
  PIN q[359]
    DIRECTION OUTPUT ;
    USE SIGNAL ;
    PORT
      LAYER M5 ;
        RECT  38.736 78.108 38.76 78.192 ;
    END
  END q[359]
  PIN q[35]
    DIRECTION OUTPUT ;
    USE SIGNAL ;
    PORT
      LAYER M5 ;
        RECT  6.576 78.108 6.6 78.192 ;
    END
  END q[35]
  PIN q[360]
    DIRECTION OUTPUT ;
    USE SIGNAL ;
    PORT
      LAYER M5 ;
        RECT  38.832 78.108 38.856 78.192 ;
    END
  END q[360]
  PIN q[361]
    DIRECTION OUTPUT ;
    USE SIGNAL ;
    PORT
      LAYER M5 ;
        RECT  38.928 78.108 38.952 78.192 ;
    END
  END q[361]
  PIN q[362]
    DIRECTION OUTPUT ;
    USE SIGNAL ;
    PORT
      LAYER M5 ;
        RECT  39.024 78.108 39.048 78.192 ;
    END
  END q[362]
  PIN q[363]
    DIRECTION OUTPUT ;
    USE SIGNAL ;
    PORT
      LAYER M5 ;
        RECT  39.12 78.108 39.144 78.192 ;
    END
  END q[363]
  PIN q[364]
    DIRECTION OUTPUT ;
    USE SIGNAL ;
    PORT
      LAYER M5 ;
        RECT  39.216 78.108 39.24 78.192 ;
    END
  END q[364]
  PIN q[365]
    DIRECTION OUTPUT ;
    USE SIGNAL ;
    PORT
      LAYER M5 ;
        RECT  39.408 78.108 39.432 78.192 ;
    END
  END q[365]
  PIN q[366]
    DIRECTION OUTPUT ;
    USE SIGNAL ;
    PORT
      LAYER M5 ;
        RECT  39.312 78.108 39.336 78.192 ;
    END
  END q[366]
  PIN q[367]
    DIRECTION OUTPUT ;
    USE SIGNAL ;
    PORT
      LAYER M5 ;
        RECT  39.6 78.108 39.624 78.192 ;
    END
  END q[367]
  PIN q[368]
    DIRECTION OUTPUT ;
    USE SIGNAL ;
    PORT
      LAYER M5 ;
        RECT  39.504 78.108 39.528 78.192 ;
    END
  END q[368]
  PIN q[369]
    DIRECTION OUTPUT ;
    USE SIGNAL ;
    PORT
      LAYER M5 ;
        RECT  39.792 78.108 39.816 78.192 ;
    END
  END q[369]
  PIN q[36]
    DIRECTION OUTPUT ;
    USE SIGNAL ;
    PORT
      LAYER M5 ;
        RECT  6.864 78.108 6.888 78.192 ;
    END
  END q[36]
  PIN q[370]
    DIRECTION OUTPUT ;
    USE SIGNAL ;
    PORT
      LAYER M5 ;
        RECT  39.696 78.108 39.72 78.192 ;
    END
  END q[370]
  PIN q[371]
    DIRECTION OUTPUT ;
    USE SIGNAL ;
    PORT
      LAYER M5 ;
        RECT  39.984 78.108 40.008 78.192 ;
    END
  END q[371]
  PIN q[372]
    DIRECTION OUTPUT ;
    USE SIGNAL ;
    PORT
      LAYER M5 ;
        RECT  39.888 78.108 39.912 78.192 ;
    END
  END q[372]
  PIN q[373]
    DIRECTION OUTPUT ;
    USE SIGNAL ;
    PORT
      LAYER M5 ;
        RECT  40.176 78.108 40.2 78.192 ;
    END
  END q[373]
  PIN q[374]
    DIRECTION OUTPUT ;
    USE SIGNAL ;
    PORT
      LAYER M5 ;
        RECT  40.08 78.108 40.104 78.192 ;
    END
  END q[374]
  PIN q[375]
    DIRECTION OUTPUT ;
    USE SIGNAL ;
    PORT
      LAYER M5 ;
        RECT  40.368 78.108 40.392 78.192 ;
    END
  END q[375]
  PIN q[376]
    DIRECTION OUTPUT ;
    USE SIGNAL ;
    PORT
      LAYER M5 ;
        RECT  40.272 78.108 40.296 78.192 ;
    END
  END q[376]
  PIN q[377]
    DIRECTION OUTPUT ;
    USE SIGNAL ;
    PORT
      LAYER M5 ;
        RECT  40.56 78.108 40.584 78.192 ;
    END
  END q[377]
  PIN q[378]
    DIRECTION OUTPUT ;
    USE SIGNAL ;
    PORT
      LAYER M5 ;
        RECT  40.464 78.108 40.488 78.192 ;
    END
  END q[378]
  PIN q[379]
    DIRECTION OUTPUT ;
    USE SIGNAL ;
    PORT
      LAYER M5 ;
        RECT  40.752 78.108 40.776 78.192 ;
    END
  END q[379]
  PIN q[37]
    DIRECTION OUTPUT ;
    USE SIGNAL ;
    PORT
      LAYER M5 ;
        RECT  6.768 78.108 6.792 78.192 ;
    END
  END q[37]
  PIN q[380]
    DIRECTION OUTPUT ;
    USE SIGNAL ;
    PORT
      LAYER M5 ;
        RECT  40.656 78.108 40.68 78.192 ;
    END
  END q[380]
  PIN q[381]
    DIRECTION OUTPUT ;
    USE SIGNAL ;
    PORT
      LAYER M5 ;
        RECT  40.944 78.108 40.968 78.192 ;
    END
  END q[381]
  PIN q[382]
    DIRECTION OUTPUT ;
    USE SIGNAL ;
    PORT
      LAYER M5 ;
        RECT  40.848 78.108 40.872 78.192 ;
    END
  END q[382]
  PIN q[383]
    DIRECTION OUTPUT ;
    USE SIGNAL ;
    PORT
      LAYER M5 ;
        RECT  41.04 78.108 41.064 78.192 ;
    END
  END q[383]
  PIN q[384]
    DIRECTION OUTPUT ;
    USE SIGNAL ;
    PORT
      LAYER M5 ;
        RECT  41.232 78.108 41.256 78.192 ;
    END
  END q[384]
  PIN q[385]
    DIRECTION OUTPUT ;
    USE SIGNAL ;
    PORT
      LAYER M5 ;
        RECT  41.136 78.108 41.16 78.192 ;
    END
  END q[385]
  PIN q[386]
    DIRECTION OUTPUT ;
    USE SIGNAL ;
    PORT
      LAYER M5 ;
        RECT  41.424 78.108 41.448 78.192 ;
    END
  END q[386]
  PIN q[387]
    DIRECTION OUTPUT ;
    USE SIGNAL ;
    PORT
      LAYER M5 ;
        RECT  41.328 78.108 41.352 78.192 ;
    END
  END q[387]
  PIN q[388]
    DIRECTION OUTPUT ;
    USE SIGNAL ;
    PORT
      LAYER M5 ;
        RECT  41.616 78.108 41.64 78.192 ;
    END
  END q[388]
  PIN q[389]
    DIRECTION OUTPUT ;
    USE SIGNAL ;
    PORT
      LAYER M5 ;
        RECT  41.52 78.108 41.544 78.192 ;
    END
  END q[389]
  PIN q[38]
    DIRECTION OUTPUT ;
    USE SIGNAL ;
    PORT
      LAYER M5 ;
        RECT  7.056 78.108 7.08 78.192 ;
    END
  END q[38]
  PIN q[390]
    DIRECTION OUTPUT ;
    USE SIGNAL ;
    PORT
      LAYER M5 ;
        RECT  41.808 78.108 41.832 78.192 ;
    END
  END q[390]
  PIN q[391]
    DIRECTION OUTPUT ;
    USE SIGNAL ;
    PORT
      LAYER M5 ;
        RECT  41.712 78.108 41.736 78.192 ;
    END
  END q[391]
  PIN q[392]
    DIRECTION OUTPUT ;
    USE SIGNAL ;
    PORT
      LAYER M5 ;
        RECT  42.096 78.108 42.12 78.192 ;
    END
  END q[392]
  PIN q[393]
    DIRECTION OUTPUT ;
    USE SIGNAL ;
    PORT
      LAYER M5 ;
        RECT  41.904 78.108 41.928 78.192 ;
    END
  END q[393]
  PIN q[394]
    DIRECTION OUTPUT ;
    USE SIGNAL ;
    PORT
      LAYER M5 ;
        RECT  42.192 78.108 42.216 78.192 ;
    END
  END q[394]
  PIN q[395]
    DIRECTION OUTPUT ;
    USE SIGNAL ;
    PORT
      LAYER M5 ;
        RECT  42 78.108 42.024 78.192 ;
    END
  END q[395]
  PIN q[396]
    DIRECTION OUTPUT ;
    USE SIGNAL ;
    PORT
      LAYER M5 ;
        RECT  42.384 78.108 42.408 78.192 ;
    END
  END q[396]
  PIN q[397]
    DIRECTION OUTPUT ;
    USE SIGNAL ;
    PORT
      LAYER M5 ;
        RECT  42.288 78.108 42.312 78.192 ;
    END
  END q[397]
  PIN q[398]
    DIRECTION OUTPUT ;
    USE SIGNAL ;
    PORT
      LAYER M5 ;
        RECT  42.576 78.108 42.6 78.192 ;
    END
  END q[398]
  PIN q[399]
    DIRECTION OUTPUT ;
    USE SIGNAL ;
    PORT
      LAYER M5 ;
        RECT  42.48 78.108 42.504 78.192 ;
    END
  END q[399]
  PIN q[39]
    DIRECTION OUTPUT ;
    USE SIGNAL ;
    PORT
      LAYER M5 ;
        RECT  6.96 78.108 6.984 78.192 ;
    END
  END q[39]
  PIN q[3]
    DIRECTION OUTPUT ;
    USE SIGNAL ;
    PORT
      LAYER M5 ;
        RECT  3.6 78.108 3.624 78.192 ;
    END
  END q[3]
  PIN q[400]
    DIRECTION OUTPUT ;
    USE SIGNAL ;
    PORT
      LAYER M5 ;
        RECT  42.672 78.108 42.696 78.192 ;
    END
  END q[400]
  PIN q[401]
    DIRECTION OUTPUT ;
    USE SIGNAL ;
    PORT
      LAYER M5 ;
        RECT  42.768 78.108 42.792 78.192 ;
    END
  END q[401]
  PIN q[402]
    DIRECTION OUTPUT ;
    USE SIGNAL ;
    PORT
      LAYER M5 ;
        RECT  42.864 78.108 42.888 78.192 ;
    END
  END q[402]
  PIN q[403]
    DIRECTION OUTPUT ;
    USE SIGNAL ;
    PORT
      LAYER M5 ;
        RECT  42.96 78.108 42.984 78.192 ;
    END
  END q[403]
  PIN q[404]
    DIRECTION OUTPUT ;
    USE SIGNAL ;
    PORT
      LAYER M5 ;
        RECT  43.056 78.108 43.08 78.192 ;
    END
  END q[404]
  PIN q[405]
    DIRECTION OUTPUT ;
    USE SIGNAL ;
    PORT
      LAYER M5 ;
        RECT  43.152 78.108 43.176 78.192 ;
    END
  END q[405]
  PIN q[406]
    DIRECTION OUTPUT ;
    USE SIGNAL ;
    PORT
      LAYER M5 ;
        RECT  43.248 78.108 43.272 78.192 ;
    END
  END q[406]
  PIN q[407]
    DIRECTION OUTPUT ;
    USE SIGNAL ;
    PORT
      LAYER M5 ;
        RECT  43.344 78.108 43.368 78.192 ;
    END
  END q[407]
  PIN q[408]
    DIRECTION OUTPUT ;
    USE SIGNAL ;
    PORT
      LAYER M5 ;
        RECT  43.44 78.108 43.464 78.192 ;
    END
  END q[408]
  PIN q[409]
    DIRECTION OUTPUT ;
    USE SIGNAL ;
    PORT
      LAYER M5 ;
        RECT  43.536 78.108 43.56 78.192 ;
    END
  END q[409]
  PIN q[40]
    DIRECTION OUTPUT ;
    USE SIGNAL ;
    PORT
      LAYER M5 ;
        RECT  7.248 78.108 7.272 78.192 ;
    END
  END q[40]
  PIN q[410]
    DIRECTION OUTPUT ;
    USE SIGNAL ;
    PORT
      LAYER M5 ;
        RECT  43.632 78.108 43.656 78.192 ;
    END
  END q[410]
  PIN q[411]
    DIRECTION OUTPUT ;
    USE SIGNAL ;
    PORT
      LAYER M5 ;
        RECT  43.728 78.108 43.752 78.192 ;
    END
  END q[411]
  PIN q[412]
    DIRECTION OUTPUT ;
    USE SIGNAL ;
    PORT
      LAYER M5 ;
        RECT  43.824 78.108 43.848 78.192 ;
    END
  END q[412]
  PIN q[413]
    DIRECTION OUTPUT ;
    USE SIGNAL ;
    PORT
      LAYER M5 ;
        RECT  43.92 78.108 43.944 78.192 ;
    END
  END q[413]
  PIN q[414]
    DIRECTION OUTPUT ;
    USE SIGNAL ;
    PORT
      LAYER M5 ;
        RECT  44.016 78.108 44.04 78.192 ;
    END
  END q[414]
  PIN q[415]
    DIRECTION OUTPUT ;
    USE SIGNAL ;
    PORT
      LAYER M5 ;
        RECT  44.208 78.108 44.232 78.192 ;
    END
  END q[415]
  PIN q[416]
    DIRECTION OUTPUT ;
    USE SIGNAL ;
    PORT
      LAYER M5 ;
        RECT  44.112 78.108 44.136 78.192 ;
    END
  END q[416]
  PIN q[417]
    DIRECTION OUTPUT ;
    USE SIGNAL ;
    PORT
      LAYER M5 ;
        RECT  44.4 78.108 44.424 78.192 ;
    END
  END q[417]
  PIN q[418]
    DIRECTION OUTPUT ;
    USE SIGNAL ;
    PORT
      LAYER M5 ;
        RECT  44.304 78.108 44.328 78.192 ;
    END
  END q[418]
  PIN q[419]
    DIRECTION OUTPUT ;
    USE SIGNAL ;
    PORT
      LAYER M5 ;
        RECT  44.592 78.108 44.616 78.192 ;
    END
  END q[419]
  PIN q[41]
    DIRECTION OUTPUT ;
    USE SIGNAL ;
    PORT
      LAYER M5 ;
        RECT  7.152 78.108 7.176 78.192 ;
    END
  END q[41]
  PIN q[420]
    DIRECTION OUTPUT ;
    USE SIGNAL ;
    PORT
      LAYER M5 ;
        RECT  44.496 78.108 44.52 78.192 ;
    END
  END q[420]
  PIN q[421]
    DIRECTION OUTPUT ;
    USE SIGNAL ;
    PORT
      LAYER M5 ;
        RECT  44.784 78.108 44.808 78.192 ;
    END
  END q[421]
  PIN q[422]
    DIRECTION OUTPUT ;
    USE SIGNAL ;
    PORT
      LAYER M5 ;
        RECT  44.688 78.108 44.712 78.192 ;
    END
  END q[422]
  PIN q[423]
    DIRECTION OUTPUT ;
    USE SIGNAL ;
    PORT
      LAYER M5 ;
        RECT  44.976 78.108 45 78.192 ;
    END
  END q[423]
  PIN q[424]
    DIRECTION OUTPUT ;
    USE SIGNAL ;
    PORT
      LAYER M5 ;
        RECT  44.88 78.108 44.904 78.192 ;
    END
  END q[424]
  PIN q[425]
    DIRECTION OUTPUT ;
    USE SIGNAL ;
    PORT
      LAYER M5 ;
        RECT  45.168 78.108 45.192 78.192 ;
    END
  END q[425]
  PIN q[426]
    DIRECTION OUTPUT ;
    USE SIGNAL ;
    PORT
      LAYER M5 ;
        RECT  45.072 78.108 45.096 78.192 ;
    END
  END q[426]
  PIN q[427]
    DIRECTION OUTPUT ;
    USE SIGNAL ;
    PORT
      LAYER M5 ;
        RECT  45.36 78.108 45.384 78.192 ;
    END
  END q[427]
  PIN q[428]
    DIRECTION OUTPUT ;
    USE SIGNAL ;
    PORT
      LAYER M5 ;
        RECT  45.264 78.108 45.288 78.192 ;
    END
  END q[428]
  PIN q[429]
    DIRECTION OUTPUT ;
    USE SIGNAL ;
    PORT
      LAYER M5 ;
        RECT  45.552 78.108 45.576 78.192 ;
    END
  END q[429]
  PIN q[42]
    DIRECTION OUTPUT ;
    USE SIGNAL ;
    PORT
      LAYER M5 ;
        RECT  7.344 78.108 7.368 78.192 ;
    END
  END q[42]
  PIN q[430]
    DIRECTION OUTPUT ;
    USE SIGNAL ;
    PORT
      LAYER M5 ;
        RECT  45.456 78.108 45.48 78.192 ;
    END
  END q[430]
  PIN q[431]
    DIRECTION OUTPUT ;
    USE SIGNAL ;
    PORT
      LAYER M5 ;
        RECT  45.744 78.108 45.768 78.192 ;
    END
  END q[431]
  PIN q[432]
    DIRECTION OUTPUT ;
    USE SIGNAL ;
    PORT
      LAYER M5 ;
        RECT  45.648 78.108 45.672 78.192 ;
    END
  END q[432]
  PIN q[433]
    DIRECTION OUTPUT ;
    USE SIGNAL ;
    PORT
      LAYER M5 ;
        RECT  45.84 78.108 45.864 78.192 ;
    END
  END q[433]
  PIN q[434]
    DIRECTION OUTPUT ;
    USE SIGNAL ;
    PORT
      LAYER M5 ;
        RECT  46.032 78.108 46.056 78.192 ;
    END
  END q[434]
  PIN q[435]
    DIRECTION OUTPUT ;
    USE SIGNAL ;
    PORT
      LAYER M5 ;
        RECT  45.936 78.108 45.96 78.192 ;
    END
  END q[435]
  PIN q[436]
    DIRECTION OUTPUT ;
    USE SIGNAL ;
    PORT
      LAYER M5 ;
        RECT  46.224 78.108 46.248 78.192 ;
    END
  END q[436]
  PIN q[437]
    DIRECTION OUTPUT ;
    USE SIGNAL ;
    PORT
      LAYER M5 ;
        RECT  46.128 78.108 46.152 78.192 ;
    END
  END q[437]
  PIN q[438]
    DIRECTION OUTPUT ;
    USE SIGNAL ;
    PORT
      LAYER M5 ;
        RECT  46.416 78.108 46.44 78.192 ;
    END
  END q[438]
  PIN q[439]
    DIRECTION OUTPUT ;
    USE SIGNAL ;
    PORT
      LAYER M5 ;
        RECT  46.32 78.108 46.344 78.192 ;
    END
  END q[439]
  PIN q[43]
    DIRECTION OUTPUT ;
    USE SIGNAL ;
    PORT
      LAYER M5 ;
        RECT  7.44 78.108 7.464 78.192 ;
    END
  END q[43]
  PIN q[440]
    DIRECTION OUTPUT ;
    USE SIGNAL ;
    PORT
      LAYER M5 ;
        RECT  46.608 78.108 46.632 78.192 ;
    END
  END q[440]
  PIN q[441]
    DIRECTION OUTPUT ;
    USE SIGNAL ;
    PORT
      LAYER M5 ;
        RECT  46.512 78.108 46.536 78.192 ;
    END
  END q[441]
  PIN q[442]
    DIRECTION OUTPUT ;
    USE SIGNAL ;
    PORT
      LAYER M5 ;
        RECT  46.8 78.108 46.824 78.192 ;
    END
  END q[442]
  PIN q[443]
    DIRECTION OUTPUT ;
    USE SIGNAL ;
    PORT
      LAYER M5 ;
        RECT  46.704 78.108 46.728 78.192 ;
    END
  END q[443]
  PIN q[444]
    DIRECTION OUTPUT ;
    USE SIGNAL ;
    PORT
      LAYER M5 ;
        RECT  46.992 78.108 47.016 78.192 ;
    END
  END q[444]
  PIN q[445]
    DIRECTION OUTPUT ;
    USE SIGNAL ;
    PORT
      LAYER M5 ;
        RECT  46.896 78.108 46.92 78.192 ;
    END
  END q[445]
  PIN q[446]
    DIRECTION OUTPUT ;
    USE SIGNAL ;
    PORT
      LAYER M5 ;
        RECT  47.184 78.108 47.208 78.192 ;
    END
  END q[446]
  PIN q[447]
    DIRECTION OUTPUT ;
    USE SIGNAL ;
    PORT
      LAYER M5 ;
        RECT  47.088 78.108 47.112 78.192 ;
    END
  END q[447]
  PIN q[448]
    DIRECTION OUTPUT ;
    USE SIGNAL ;
    PORT
      LAYER M5 ;
        RECT  47.28 78.108 47.304 78.192 ;
    END
  END q[448]
  PIN q[449]
    DIRECTION OUTPUT ;
    USE SIGNAL ;
    PORT
      LAYER M5 ;
        RECT  47.376 78.108 47.4 78.192 ;
    END
  END q[449]
  PIN q[44]
    DIRECTION OUTPUT ;
    USE SIGNAL ;
    PORT
      LAYER M5 ;
        RECT  7.536 78.108 7.56 78.192 ;
    END
  END q[44]
  PIN q[450]
    DIRECTION OUTPUT ;
    USE SIGNAL ;
    PORT
      LAYER M5 ;
        RECT  47.472 78.108 47.496 78.192 ;
    END
  END q[450]
  PIN q[451]
    DIRECTION OUTPUT ;
    USE SIGNAL ;
    PORT
      LAYER M5 ;
        RECT  47.568 78.108 47.592 78.192 ;
    END
  END q[451]
  PIN q[452]
    DIRECTION OUTPUT ;
    USE SIGNAL ;
    PORT
      LAYER M5 ;
        RECT  47.664 78.108 47.688 78.192 ;
    END
  END q[452]
  PIN q[453]
    DIRECTION OUTPUT ;
    USE SIGNAL ;
    PORT
      LAYER M5 ;
        RECT  47.76 78.108 47.784 78.192 ;
    END
  END q[453]
  PIN q[454]
    DIRECTION OUTPUT ;
    USE SIGNAL ;
    PORT
      LAYER M5 ;
        RECT  47.856 78.108 47.88 78.192 ;
    END
  END q[454]
  PIN q[455]
    DIRECTION OUTPUT ;
    USE SIGNAL ;
    PORT
      LAYER M5 ;
        RECT  47.952 78.108 47.976 78.192 ;
    END
  END q[455]
  PIN q[456]
    DIRECTION OUTPUT ;
    USE SIGNAL ;
    PORT
      LAYER M5 ;
        RECT  48.048 78.108 48.072 78.192 ;
    END
  END q[456]
  PIN q[45]
    DIRECTION OUTPUT ;
    USE SIGNAL ;
    PORT
      LAYER M5 ;
        RECT  7.632 78.108 7.656 78.192 ;
    END
  END q[45]
  PIN q[46]
    DIRECTION OUTPUT ;
    USE SIGNAL ;
    PORT
      LAYER M5 ;
        RECT  7.728 78.108 7.752 78.192 ;
    END
  END q[46]
  PIN q[47]
    DIRECTION OUTPUT ;
    USE SIGNAL ;
    PORT
      LAYER M5 ;
        RECT  7.824 78.108 7.848 78.192 ;
    END
  END q[47]
  PIN q[48]
    DIRECTION OUTPUT ;
    USE SIGNAL ;
    PORT
      LAYER M5 ;
        RECT  7.92 78.108 7.944 78.192 ;
    END
  END q[48]
  PIN q[49]
    DIRECTION OUTPUT ;
    USE SIGNAL ;
    PORT
      LAYER M5 ;
        RECT  8.016 78.108 8.04 78.192 ;
    END
  END q[49]
  PIN q[4]
    DIRECTION OUTPUT ;
    USE SIGNAL ;
    PORT
      LAYER M5 ;
        RECT  3.696 78.108 3.72 78.192 ;
    END
  END q[4]
  PIN q[50]
    DIRECTION OUTPUT ;
    USE SIGNAL ;
    PORT
      LAYER M5 ;
        RECT  8.112 78.108 8.136 78.192 ;
    END
  END q[50]
  PIN q[51]
    DIRECTION OUTPUT ;
    USE SIGNAL ;
    PORT
      LAYER M5 ;
        RECT  8.208 78.108 8.232 78.192 ;
    END
  END q[51]
  PIN q[52]
    DIRECTION OUTPUT ;
    USE SIGNAL ;
    PORT
      LAYER M5 ;
        RECT  8.304 78.108 8.328 78.192 ;
    END
  END q[52]
  PIN q[53]
    DIRECTION OUTPUT ;
    USE SIGNAL ;
    PORT
      LAYER M5 ;
        RECT  8.4 78.108 8.424 78.192 ;
    END
  END q[53]
  PIN q[54]
    DIRECTION OUTPUT ;
    USE SIGNAL ;
    PORT
      LAYER M5 ;
        RECT  8.496 78.108 8.52 78.192 ;
    END
  END q[54]
  PIN q[55]
    DIRECTION OUTPUT ;
    USE SIGNAL ;
    PORT
      LAYER M5 ;
        RECT  8.592 78.108 8.616 78.192 ;
    END
  END q[55]
  PIN q[56]
    DIRECTION OUTPUT ;
    USE SIGNAL ;
    PORT
      LAYER M5 ;
        RECT  8.688 78.108 8.712 78.192 ;
    END
  END q[56]
  PIN q[57]
    DIRECTION OUTPUT ;
    USE SIGNAL ;
    PORT
      LAYER M5 ;
        RECT  8.784 78.108 8.808 78.192 ;
    END
  END q[57]
  PIN q[58]
    DIRECTION OUTPUT ;
    USE SIGNAL ;
    PORT
      LAYER M5 ;
        RECT  8.88 78.108 8.904 78.192 ;
    END
  END q[58]
  PIN q[59]
    DIRECTION OUTPUT ;
    USE SIGNAL ;
    PORT
      LAYER M5 ;
        RECT  8.976 78.108 9 78.192 ;
    END
  END q[59]
  PIN q[5]
    DIRECTION OUTPUT ;
    USE SIGNAL ;
    PORT
      LAYER M5 ;
        RECT  3.792 78.108 3.816 78.192 ;
    END
  END q[5]
  PIN q[60]
    DIRECTION OUTPUT ;
    USE SIGNAL ;
    PORT
      LAYER M5 ;
        RECT  9.072 78.108 9.096 78.192 ;
    END
  END q[60]
  PIN q[61]
    DIRECTION OUTPUT ;
    USE SIGNAL ;
    PORT
      LAYER M5 ;
        RECT  9.264 78.108 9.288 78.192 ;
    END
  END q[61]
  PIN q[62]
    DIRECTION OUTPUT ;
    USE SIGNAL ;
    PORT
      LAYER M5 ;
        RECT  9.168 78.108 9.192 78.192 ;
    END
  END q[62]
  PIN q[63]
    DIRECTION OUTPUT ;
    USE SIGNAL ;
    PORT
      LAYER M5 ;
        RECT  9.456 78.108 9.48 78.192 ;
    END
  END q[63]
  PIN q[64]
    DIRECTION OUTPUT ;
    USE SIGNAL ;
    PORT
      LAYER M5 ;
        RECT  9.36 78.108 9.384 78.192 ;
    END
  END q[64]
  PIN q[65]
    DIRECTION OUTPUT ;
    USE SIGNAL ;
    PORT
      LAYER M5 ;
        RECT  9.648 78.108 9.672 78.192 ;
    END
  END q[65]
  PIN q[66]
    DIRECTION OUTPUT ;
    USE SIGNAL ;
    PORT
      LAYER M5 ;
        RECT  9.552 78.108 9.576 78.192 ;
    END
  END q[66]
  PIN q[67]
    DIRECTION OUTPUT ;
    USE SIGNAL ;
    PORT
      LAYER M5 ;
        RECT  9.84 78.108 9.864 78.192 ;
    END
  END q[67]
  PIN q[68]
    DIRECTION OUTPUT ;
    USE SIGNAL ;
    PORT
      LAYER M5 ;
        RECT  9.744 78.108 9.768 78.192 ;
    END
  END q[68]
  PIN q[69]
    DIRECTION OUTPUT ;
    USE SIGNAL ;
    PORT
      LAYER M5 ;
        RECT  10.032 78.108 10.056 78.192 ;
    END
  END q[69]
  PIN q[6]
    DIRECTION OUTPUT ;
    USE SIGNAL ;
    PORT
      LAYER M5 ;
        RECT  3.888 78.108 3.912 78.192 ;
    END
  END q[6]
  PIN q[70]
    DIRECTION OUTPUT ;
    USE SIGNAL ;
    PORT
      LAYER M5 ;
        RECT  9.936 78.108 9.96 78.192 ;
    END
  END q[70]
  PIN q[71]
    DIRECTION OUTPUT ;
    USE SIGNAL ;
    PORT
      LAYER M5 ;
        RECT  10.224 78.108 10.248 78.192 ;
    END
  END q[71]
  PIN q[72]
    DIRECTION OUTPUT ;
    USE SIGNAL ;
    PORT
      LAYER M5 ;
        RECT  10.128 78.108 10.152 78.192 ;
    END
  END q[72]
  PIN q[73]
    DIRECTION OUTPUT ;
    USE SIGNAL ;
    PORT
      LAYER M5 ;
        RECT  10.416 78.108 10.44 78.192 ;
    END
  END q[73]
  PIN q[74]
    DIRECTION OUTPUT ;
    USE SIGNAL ;
    PORT
      LAYER M5 ;
        RECT  10.32 78.108 10.344 78.192 ;
    END
  END q[74]
  PIN q[75]
    DIRECTION OUTPUT ;
    USE SIGNAL ;
    PORT
      LAYER M5 ;
        RECT  10.704 78.108 10.728 78.192 ;
    END
  END q[75]
  PIN q[76]
    DIRECTION OUTPUT ;
    USE SIGNAL ;
    PORT
      LAYER M5 ;
        RECT  10.512 78.108 10.536 78.192 ;
    END
  END q[76]
  PIN q[77]
    DIRECTION OUTPUT ;
    USE SIGNAL ;
    PORT
      LAYER M5 ;
        RECT  10.896 78.108 10.92 78.192 ;
    END
  END q[77]
  PIN q[78]
    DIRECTION OUTPUT ;
    USE SIGNAL ;
    PORT
      LAYER M5 ;
        RECT  10.608 78.108 10.632 78.192 ;
    END
  END q[78]
  PIN q[79]
    DIRECTION OUTPUT ;
    USE SIGNAL ;
    PORT
      LAYER M5 ;
        RECT  10.992 78.108 11.016 78.192 ;
    END
  END q[79]
  PIN q[7]
    DIRECTION OUTPUT ;
    USE SIGNAL ;
    PORT
      LAYER M5 ;
        RECT  3.984 78.108 4.008 78.192 ;
    END
  END q[7]
  PIN q[80]
    DIRECTION OUTPUT ;
    USE SIGNAL ;
    PORT
      LAYER M5 ;
        RECT  10.8 78.108 10.824 78.192 ;
    END
  END q[80]
  PIN q[81]
    DIRECTION OUTPUT ;
    USE SIGNAL ;
    PORT
      LAYER M5 ;
        RECT  11.088 78.108 11.112 78.192 ;
    END
  END q[81]
  PIN q[82]
    DIRECTION OUTPUT ;
    USE SIGNAL ;
    PORT
      LAYER M5 ;
        RECT  11.28 78.108 11.304 78.192 ;
    END
  END q[82]
  PIN q[83]
    DIRECTION OUTPUT ;
    USE SIGNAL ;
    PORT
      LAYER M5 ;
        RECT  11.184 78.108 11.208 78.192 ;
    END
  END q[83]
  PIN q[84]
    DIRECTION OUTPUT ;
    USE SIGNAL ;
    PORT
      LAYER M5 ;
        RECT  11.472 78.108 11.496 78.192 ;
    END
  END q[84]
  PIN q[85]
    DIRECTION OUTPUT ;
    USE SIGNAL ;
    PORT
      LAYER M5 ;
        RECT  11.376 78.108 11.4 78.192 ;
    END
  END q[85]
  PIN q[86]
    DIRECTION OUTPUT ;
    USE SIGNAL ;
    PORT
      LAYER M5 ;
        RECT  11.664 78.108 11.688 78.192 ;
    END
  END q[86]
  PIN q[87]
    DIRECTION OUTPUT ;
    USE SIGNAL ;
    PORT
      LAYER M5 ;
        RECT  11.568 78.108 11.592 78.192 ;
    END
  END q[87]
  PIN q[88]
    DIRECTION OUTPUT ;
    USE SIGNAL ;
    PORT
      LAYER M5 ;
        RECT  11.856 78.108 11.88 78.192 ;
    END
  END q[88]
  PIN q[89]
    DIRECTION OUTPUT ;
    USE SIGNAL ;
    PORT
      LAYER M5 ;
        RECT  11.76 78.108 11.784 78.192 ;
    END
  END q[89]
  PIN q[8]
    DIRECTION OUTPUT ;
    USE SIGNAL ;
    PORT
      LAYER M5 ;
        RECT  4.08 78.108 4.104 78.192 ;
    END
  END q[8]
  PIN q[90]
    DIRECTION OUTPUT ;
    USE SIGNAL ;
    PORT
      LAYER M5 ;
        RECT  12.048 78.108 12.072 78.192 ;
    END
  END q[90]
  PIN q[91]
    DIRECTION OUTPUT ;
    USE SIGNAL ;
    PORT
      LAYER M5 ;
        RECT  11.952 78.108 11.976 78.192 ;
    END
  END q[91]
  PIN q[92]
    DIRECTION OUTPUT ;
    USE SIGNAL ;
    PORT
      LAYER M5 ;
        RECT  12.24 78.108 12.264 78.192 ;
    END
  END q[92]
  PIN q[93]
    DIRECTION OUTPUT ;
    USE SIGNAL ;
    PORT
      LAYER M5 ;
        RECT  12.144 78.108 12.168 78.192 ;
    END
  END q[93]
  PIN q[94]
    DIRECTION OUTPUT ;
    USE SIGNAL ;
    PORT
      LAYER M5 ;
        RECT  12.432 78.108 12.456 78.192 ;
    END
  END q[94]
  PIN q[95]
    DIRECTION OUTPUT ;
    USE SIGNAL ;
    PORT
      LAYER M5 ;
        RECT  12.336 78.108 12.36 78.192 ;
    END
  END q[95]
  PIN q[96]
    DIRECTION OUTPUT ;
    USE SIGNAL ;
    PORT
      LAYER M5 ;
        RECT  12.528 78.108 12.552 78.192 ;
    END
  END q[96]
  PIN q[97]
    DIRECTION OUTPUT ;
    USE SIGNAL ;
    PORT
      LAYER M5 ;
        RECT  12.624 78.108 12.648 78.192 ;
    END
  END q[97]
  PIN q[98]
    DIRECTION OUTPUT ;
    USE SIGNAL ;
    PORT
      LAYER M5 ;
        RECT  12.72 78.108 12.744 78.192 ;
    END
  END q[98]
  PIN q[99]
    DIRECTION OUTPUT ;
    USE SIGNAL ;
    PORT
      LAYER M5 ;
        RECT  12.816 78.108 12.84 78.192 ;
    END
  END q[99]
  PIN q[9]
    DIRECTION OUTPUT ;
    USE SIGNAL ;
    PORT
      LAYER M5 ;
        RECT  4.272 78.108 4.296 78.192 ;
    END
  END q[9]
  PIN ready
    DIRECTION OUTPUT ;
    USE SIGNAL ;
    PORT
      LAYER M5 ;
        RECT  25.392 78.108 25.416 78.192 ;
    END
  END ready
  PIN rst_n
    DIRECTION INPUT ;
    USE SIGNAL ;
    PORT
      LAYER M5 ;
        RECT  25.296 78.108 25.32 78.192 ;
    END
  END rst_n
  PIN strap_k[0]
    DIRECTION INPUT ;
    USE SIGNAL ;
    PORT
      LAYER M5 ;
        RECT  25.584 78.108 25.608 78.192 ;
    END
  END strap_k[0]
  PIN strap_k[1]
    DIRECTION INPUT ;
    USE SIGNAL ;
    PORT
      LAYER M5 ;
        RECT  25.68 78.108 25.704 78.192 ;
    END
  END strap_k[1]
  PIN strap_k[2]
    DIRECTION INPUT ;
    USE SIGNAL ;
    PORT
      LAYER M5 ;
        RECT  25.776 78.108 25.8 78.192 ;
    END
  END strap_k[2]
  PIN strap_k[3]
    DIRECTION INPUT ;
    USE SIGNAL ;
    PORT
      LAYER M5 ;
        RECT  25.872 78.108 25.896 78.192 ;
    END
  END strap_k[3]
  PIN strap_k[4]
    DIRECTION INPUT ;
    USE SIGNAL ;
    PORT
      LAYER M5 ;
        RECT  25.968 78.108 25.992 78.192 ;
    END
  END strap_k[4]
  PIN strap_k[5]
    DIRECTION INPUT ;
    USE SIGNAL ;
    PORT
      LAYER M5 ;
        RECT  26.064 78.108 26.088 78.192 ;
    END
  END strap_k[5]
  PIN t_rst_n
    DIRECTION INPUT ;
    USE SIGNAL ;
    PORT
      LAYER M5 ;
        RECT  25.68 0 25.704 0.084 ;
    END
  END t_rst_n
  PIN VDD
    DIRECTION INOUT ;
    USE POWER ;
    PORT
      LAYER M5 ;
        RECT  45.396 4.311 45.516 73.733 ;
        RECT  41.076 4.311 41.196 73.733 ;
        RECT  36.756 4.311 36.876 73.733 ;
        RECT  32.436 4.311 32.556 73.733 ;
        RECT  28.116 4.311 28.236 73.733 ;
        RECT  23.796 4.311 23.916 73.733 ;
        RECT  19.476 4.311 19.596 73.733 ;
        RECT  15.156 4.311 15.276 73.733 ;
        RECT  10.836 4.311 10.956 73.733 ;
        RECT  6.516 4.311 6.636 73.733 ;
    END
  END VDD
  PIN VSS
    DIRECTION INOUT ;
    USE GROUND ;
    PORT
      LAYER M5 ;
        RECT  45.204 4.297 45.324 73.719 ;
        RECT  40.884 4.297 41.004 73.719 ;
        RECT  36.564 4.297 36.684 73.719 ;
        RECT  32.244 4.297 32.364 73.719 ;
        RECT  27.924 4.297 28.044 73.719 ;
        RECT  23.604 4.297 23.724 73.719 ;
        RECT  19.284 4.297 19.404 73.719 ;
        RECT  14.964 4.297 15.084 73.719 ;
        RECT  10.644 4.297 10.764 73.719 ;
        RECT  6.324 4.297 6.444 73.719 ;
    END
  END VSS
  OBS
    LAYER RVTN ;
     RECT  3.301 0 48.089 78.192 ;
    LAYER RVTP ;
     RECT  3.301 0 48.089 78.192 ;
    LAYER M1 ;
     RECT  3.301 0 48.089 78.192 ;
    LAYER M2 ;
     RECT  3.301 0 48.089 78.192 ;
    LAYER M3 ;
     RECT  3.301 0 48.089 78.192 ;
    LAYER M4 ;
     RECT  3.301 0 48.089 78.192 ;
    LAYER M5 ;
     RECT  3.301 0 48.089 78.192 ;
  END
END sle_cland_w457_s
END LIBRARY
